VERSION 5.7 ;
  NOWIREEXTENSIONATPIN ON ;
  DIVIDERCHAR "/" ;
  BUSBITCHARS "[]" ;
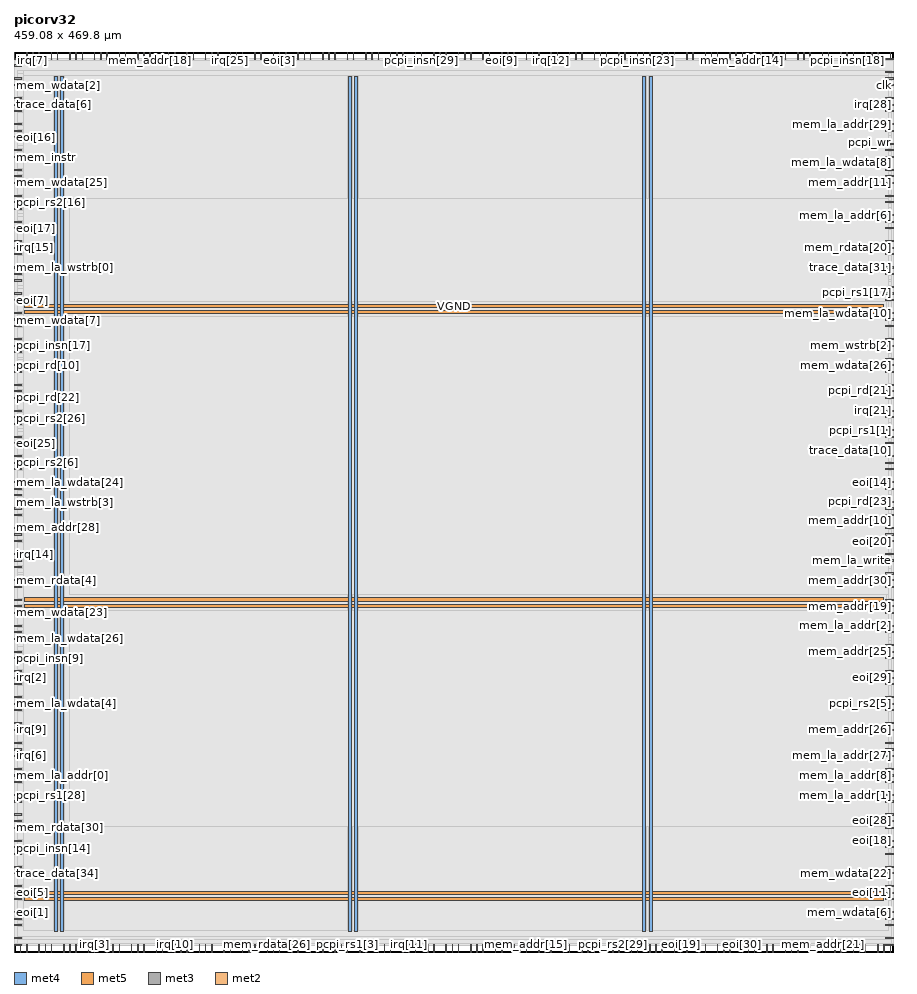
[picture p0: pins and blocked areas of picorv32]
MACRO picorv32
  CLASS BLOCK ;
  FOREIGN picorv32 ;
  ORIGIN 0.000 0.000 ;
  SIZE 459.080 BY 469.800 ;
  PIN VGND
    DIRECTION INOUT ;
    USE GROUND ;
    PORT
      LAYER met4 ;
        RECT 24.340 10.640 25.940 457.200 ;
    END
    PORT
      LAYER met4 ;
        RECT 177.940 10.640 179.540 457.200 ;
    END
    PORT
      LAYER met4 ;
        RECT 331.540 10.640 333.140 457.200 ;
    END
    PORT
      LAYER met5 ;
        RECT 5.280 30.030 453.800 31.630 ;
    END
    PORT
      LAYER met5 ;
        RECT 5.280 183.210 453.800 184.810 ;
    END
    PORT
      LAYER met5 ;
        RECT 5.280 336.390 453.800 337.990 ;
    END
  END VGND
  PIN VPWR
    DIRECTION INOUT ;
    USE POWER ;
    PORT
      LAYER met4 ;
        RECT 21.040 10.640 22.640 457.200 ;
    END
    PORT
      LAYER met4 ;
        RECT 174.640 10.640 176.240 457.200 ;
    END
    PORT
      LAYER met4 ;
        RECT 328.240 10.640 329.840 457.200 ;
    END
    PORT
      LAYER met5 ;
        RECT 5.280 26.730 453.800 28.330 ;
    END
    PORT
      LAYER met5 ;
        RECT 5.280 179.910 453.800 181.510 ;
    END
    PORT
      LAYER met5 ;
        RECT 5.280 333.090 453.800 334.690 ;
    END
  END VPWR
  PIN clk
    DIRECTION INPUT ;
    USE SIGNAL ;
    ANTENNAGATEAREA 1.286700 ;
    ANTENNADIFFAREA 0.434700 ;
    PORT
      LAYER met3 ;
        RECT 455.080 452.240 459.080 452.840 ;
    END
  END clk
  PIN eoi[0]
    DIRECTION OUTPUT TRISTATE ;
    USE SIGNAL ;
    PORT
      LAYER met3 ;
        RECT 0.000 455.640 4.000 456.240 ;
    END
  END eoi[0]
  PIN eoi[10]
    DIRECTION OUTPUT TRISTATE ;
    USE SIGNAL ;
    PORT
      LAYER met2 ;
        RECT 122.450 0.000 122.730 4.000 ;
    END
  END eoi[10]
  PIN eoi[11]
    DIRECTION OUTPUT TRISTATE ;
    USE SIGNAL ;
    PORT
      LAYER met3 ;
        RECT 455.080 30.640 459.080 31.240 ;
    END
  END eoi[11]
  PIN eoi[12]
    DIRECTION OUTPUT TRISTATE ;
    USE SIGNAL ;
    PORT
      LAYER met3 ;
        RECT 455.080 292.440 459.080 293.040 ;
    END
  END eoi[12]
  PIN eoi[13]
    DIRECTION OUTPUT TRISTATE ;
    USE SIGNAL ;
    PORT
      LAYER met2 ;
        RECT 396.150 465.800 396.430 469.800 ;
    END
  END eoi[13]
  PIN eoi[14]
    DIRECTION OUTPUT TRISTATE ;
    USE SIGNAL ;
    PORT
      LAYER met3 ;
        RECT 455.080 244.840 459.080 245.440 ;
    END
  END eoi[14]
  PIN eoi[15]
    DIRECTION OUTPUT TRISTATE ;
    USE SIGNAL ;
    PORT
      LAYER met3 ;
        RECT 455.080 78.240 459.080 78.840 ;
    END
  END eoi[15]
  PIN eoi[16]
    DIRECTION OUTPUT TRISTATE ;
    USE SIGNAL ;
    PORT
      LAYER met3 ;
        RECT 0.000 425.040 4.000 425.640 ;
    END
  END eoi[16]
  PIN eoi[17]
    DIRECTION OUTPUT TRISTATE ;
    USE SIGNAL ;
    PORT
      LAYER met3 ;
        RECT 0.000 377.440 4.000 378.040 ;
    END
  END eoi[17]
  PIN eoi[18]
    DIRECTION OUTPUT TRISTATE ;
    USE SIGNAL ;
    PORT
      LAYER met3 ;
        RECT 455.080 57.840 459.080 58.440 ;
    END
  END eoi[18]
  PIN eoi[19]
    DIRECTION OUTPUT TRISTATE ;
    USE SIGNAL ;
    PORT
      LAYER met2 ;
        RECT 347.850 0.000 348.130 4.000 ;
    END
  END eoi[19]
  PIN eoi[1]
    DIRECTION OUTPUT TRISTATE ;
    USE SIGNAL ;
    PORT
      LAYER met3 ;
        RECT 0.000 20.440 4.000 21.040 ;
    END
  END eoi[1]
  PIN eoi[20]
    DIRECTION OUTPUT TRISTATE ;
    USE SIGNAL ;
    PORT
      LAYER met3 ;
        RECT 455.080 214.240 459.080 214.840 ;
    END
  END eoi[20]
  PIN eoi[21]
    DIRECTION OUTPUT TRISTATE ;
    USE SIGNAL ;
    PORT
      LAYER met2 ;
        RECT 457.330 0.000 457.610 4.000 ;
    END
  END eoi[21]
  PIN eoi[22]
    DIRECTION OUTPUT TRISTATE ;
    USE SIGNAL ;
    PORT
      LAYER met3 ;
        RECT 0.000 428.440 4.000 429.040 ;
    END
  END eoi[22]
  PIN eoi[23]
    DIRECTION OUTPUT TRISTATE ;
    USE SIGNAL ;
    PORT
      LAYER met3 ;
        RECT 455.080 88.440 459.080 89.040 ;
    END
  END eoi[23]
  PIN eoi[24]
    DIRECTION OUTPUT TRISTATE ;
    USE SIGNAL ;
    PORT
      LAYER met2 ;
        RECT 51.610 0.000 51.890 4.000 ;
    END
  END eoi[24]
  PIN eoi[25]
    DIRECTION OUTPUT TRISTATE ;
    USE SIGNAL ;
    PORT
      LAYER met3 ;
        RECT 0.000 265.240 4.000 265.840 ;
    END
  END eoi[25]
  PIN eoi[26]
    DIRECTION OUTPUT TRISTATE ;
    USE SIGNAL ;
    PORT
      LAYER met2 ;
        RECT 190.070 465.800 190.350 469.800 ;
    END
  END eoi[26]
  PIN eoi[27]
    DIRECTION OUTPUT TRISTATE ;
    USE SIGNAL ;
    PORT
      LAYER met3 ;
        RECT 0.000 34.040 4.000 34.640 ;
    END
  END eoi[27]
  PIN eoi[28]
    DIRECTION OUTPUT TRISTATE ;
    USE SIGNAL ;
    PORT
      LAYER met3 ;
        RECT 455.080 64.640 459.080 65.240 ;
    END
  END eoi[28]
  PIN eoi[29]
    DIRECTION OUTPUT TRISTATE ;
    USE SIGNAL ;
    PORT
      LAYER met3 ;
        RECT 455.080 142.840 459.080 143.440 ;
    END
  END eoi[29]
  PIN eoi[2]
    DIRECTION OUTPUT TRISTATE ;
    USE SIGNAL ;
    PORT
      LAYER met3 ;
        RECT 455.080 353.640 459.080 354.240 ;
    END
  END eoi[2]
  PIN eoi[30]
    DIRECTION OUTPUT TRISTATE ;
    USE SIGNAL ;
    PORT
      LAYER met2 ;
        RECT 380.050 0.000 380.330 4.000 ;
    END
  END eoi[30]
  PIN eoi[31]
    DIRECTION OUTPUT TRISTATE ;
    USE SIGNAL ;
    PORT
      LAYER met3 ;
        RECT 455.080 241.440 459.080 242.040 ;
    END
  END eoi[31]
  PIN eoi[3]
    DIRECTION OUTPUT TRISTATE ;
    USE SIGNAL ;
    PORT
      LAYER met2 ;
        RECT 138.550 465.800 138.830 469.800 ;
    END
  END eoi[3]
  PIN eoi[4]
    DIRECTION OUTPUT TRISTATE ;
    USE SIGNAL ;
    PORT
      LAYER met2 ;
        RECT 373.610 0.000 373.890 4.000 ;
    END
  END eoi[4]
  PIN eoi[5]
    DIRECTION OUTPUT TRISTATE ;
    USE SIGNAL ;
    PORT
      LAYER met3 ;
        RECT 0.000 30.640 4.000 31.240 ;
    END
  END eoi[5]
  PIN eoi[6]
    DIRECTION OUTPUT TRISTATE ;
    USE SIGNAL ;
    PORT
      LAYER met2 ;
        RECT 360.730 0.000 361.010 4.000 ;
    END
  END eoi[6]
  PIN eoi[7]
    DIRECTION OUTPUT TRISTATE ;
    USE SIGNAL ;
    PORT
      LAYER met3 ;
        RECT 0.000 340.040 4.000 340.640 ;
    END
  END eoi[7]
  PIN eoi[8]
    DIRECTION OUTPUT TRISTATE ;
    USE SIGNAL ;
    PORT
      LAYER met2 ;
        RECT 338.190 465.800 338.470 469.800 ;
    END
  END eoi[8]
  PIN eoi[9]
    DIRECTION OUTPUT TRISTATE ;
    USE SIGNAL ;
    PORT
      LAYER met2 ;
        RECT 254.470 465.800 254.750 469.800 ;
    END
  END eoi[9]
  PIN irq[0]
    DIRECTION INPUT ;
    USE SIGNAL ;
    PORT
      LAYER met3 ;
        RECT 455.080 183.640 459.080 184.240 ;
    END
  END irq[0]
  PIN irq[10]
    DIRECTION INPUT ;
    USE SIGNAL ;
    PORT
      LAYER met2 ;
        RECT 83.810 0.000 84.090 4.000 ;
    END
  END irq[10]
  PIN irq[11]
    DIRECTION INPUT ;
    USE SIGNAL ;
    PORT
      LAYER met2 ;
        RECT 206.170 0.000 206.450 4.000 ;
    END
  END irq[11]
  PIN irq[12]
    DIRECTION INPUT ;
    USE SIGNAL ;
    PORT
      LAYER met2 ;
        RECT 280.230 465.800 280.510 469.800 ;
    END
  END irq[12]
  PIN irq[13]
    DIRECTION INPUT ;
    USE SIGNAL ;
    PORT
      LAYER met2 ;
        RECT 444.450 465.800 444.730 469.800 ;
    END
  END irq[13]
  PIN irq[14]
    DIRECTION INPUT ;
    USE SIGNAL ;
    PORT
      LAYER met3 ;
        RECT 0.000 207.440 4.000 208.040 ;
    END
  END irq[14]
  PIN irq[15]
    DIRECTION INPUT ;
    USE SIGNAL ;
    PORT
      LAYER met3 ;
        RECT 0.000 367.240 4.000 367.840 ;
    END
  END irq[15]
  PIN irq[16]
    DIRECTION INPUT ;
    USE SIGNAL ;
    PORT
      LAYER met2 ;
        RECT 457.330 465.800 457.610 469.800 ;
    END
  END irq[16]
  PIN irq[17]
    DIRECTION INPUT ;
    USE SIGNAL ;
    PORT
      LAYER met2 ;
        RECT 257.690 465.800 257.970 469.800 ;
    END
  END irq[17]
  PIN irq[18]
    DIRECTION INPUT ;
    USE SIGNAL ;
    PORT
      LAYER met2 ;
        RECT 344.630 465.800 344.910 469.800 ;
    END
  END irq[18]
  PIN irq[19]
    DIRECTION INPUT ;
    USE SIGNAL ;
    PORT
      LAYER met3 ;
        RECT 0.000 431.840 4.000 432.440 ;
    END
  END irq[19]
  PIN irq[1]
    DIRECTION INPUT ;
    USE SIGNAL ;
    PORT
      LAYER met2 ;
        RECT 309.210 0.000 309.490 4.000 ;
    END
  END irq[1]
  PIN irq[20]
    DIRECTION INPUT ;
    USE SIGNAL ;
    PORT
      LAYER met3 ;
        RECT 0.000 465.840 4.000 466.440 ;
    END
  END irq[20]
  PIN irq[21]
    DIRECTION INPUT ;
    USE SIGNAL ;
    PORT
      LAYER met3 ;
        RECT 455.080 282.240 459.080 282.840 ;
    END
  END irq[21]
  PIN irq[22]
    DIRECTION INPUT ;
    USE SIGNAL ;
    PORT
      LAYER met2 ;
        RECT 154.650 0.000 154.930 4.000 ;
    END
  END irq[22]
  PIN irq[23]
    DIRECTION INPUT ;
    USE SIGNAL ;
    PORT
      LAYER met3 ;
        RECT 0.000 275.440 4.000 276.040 ;
    END
  END irq[23]
  PIN irq[24]
    DIRECTION INPUT ;
    USE SIGNAL ;
    PORT
      LAYER met3 ;
        RECT 455.080 465.840 459.080 466.440 ;
    END
  END irq[24]
  PIN irq[25]
    DIRECTION INPUT ;
    USE SIGNAL ;
    PORT
      LAYER met2 ;
        RECT 112.790 465.800 113.070 469.800 ;
    END
  END irq[25]
  PIN irq[26]
    DIRECTION INPUT ;
    USE SIGNAL ;
    PORT
      LAYER met2 ;
        RECT 190.070 0.000 190.350 4.000 ;
    END
  END irq[26]
  PIN irq[27]
    DIRECTION INPUT ;
    USE SIGNAL ;
    PORT
      LAYER met2 ;
        RECT 231.930 465.800 232.210 469.800 ;
    END
  END irq[27]
  PIN irq[28]
    DIRECTION INPUT ;
    USE SIGNAL ;
    PORT
      LAYER met3 ;
        RECT 455.080 442.040 459.080 442.640 ;
    END
  END irq[28]
  PIN irq[29]
    DIRECTION INPUT ;
    USE SIGNAL ;
    PORT
      LAYER met3 ;
        RECT 455.080 54.440 459.080 55.040 ;
    END
  END irq[29]
  PIN irq[2]
    DIRECTION INPUT ;
    USE SIGNAL ;
    PORT
      LAYER met3 ;
        RECT 0.000 142.840 4.000 143.440 ;
    END
  END irq[2]
  PIN irq[30]
    DIRECTION INPUT ;
    USE SIGNAL ;
    PORT
      LAYER met2 ;
        RECT 264.130 0.000 264.410 4.000 ;
    END
  END irq[30]
  PIN irq[31]
    DIRECTION INPUT ;
    USE SIGNAL ;
    PORT
      LAYER met2 ;
        RECT 106.350 465.800 106.630 469.800 ;
    END
  END irq[31]
  PIN irq[3]
    DIRECTION INPUT ;
    USE SIGNAL ;
    PORT
      LAYER met2 ;
        RECT 41.950 0.000 42.230 4.000 ;
    END
  END irq[3]
  PIN irq[4]
    DIRECTION INPUT ;
    USE SIGNAL ;
    PORT
      LAYER met2 ;
        RECT 90.250 465.800 90.530 469.800 ;
    END
  END irq[4]
  PIN irq[5]
    DIRECTION INPUT ;
    USE SIGNAL ;
    PORT
      LAYER met3 ;
        RECT 455.080 414.840 459.080 415.440 ;
    END
  END irq[5]
  PIN irq[6]
    DIRECTION INPUT ;
    USE SIGNAL ;
    PORT
      LAYER met3 ;
        RECT 0.000 102.040 4.000 102.640 ;
    END
  END irq[6]
  PIN irq[7]
    DIRECTION INPUT ;
    USE SIGNAL ;
    PORT
      LAYER met2 ;
        RECT 9.750 465.800 10.030 469.800 ;
    END
  END irq[7]
  PIN irq[8]
    DIRECTION INPUT ;
    USE SIGNAL ;
    PORT
      LAYER met2 ;
        RECT 322.090 0.000 322.370 4.000 ;
    END
  END irq[8]
  PIN irq[9]
    DIRECTION INPUT ;
    USE SIGNAL ;
    PORT
      LAYER met3 ;
        RECT 0.000 115.640 4.000 116.240 ;
    END
  END irq[9]
  PIN mem_addr[0]
    DIRECTION OUTPUT TRISTATE ;
    USE SIGNAL ;
    PORT
      LAYER met3 ;
        RECT 455.080 13.640 459.080 14.240 ;
    END
  END mem_addr[0]
  PIN mem_addr[10]
    DIRECTION OUTPUT TRISTATE ;
    USE SIGNAL ;
    ANTENNADIFFAREA 0.795200 ;
    PORT
      LAYER met3 ;
        RECT 455.080 221.040 459.080 221.640 ;
    END
  END mem_addr[10]
  PIN mem_addr[11]
    DIRECTION OUTPUT TRISTATE ;
    USE SIGNAL ;
    ANTENNADIFFAREA 0.445500 ;
    PORT
      LAYER met3 ;
        RECT 455.080 401.240 459.080 401.840 ;
    END
  END mem_addr[11]
  PIN mem_addr[12]
    DIRECTION OUTPUT TRISTATE ;
    USE SIGNAL ;
    ANTENNADIFFAREA 0.445500 ;
    PORT
      LAYER met3 ;
        RECT 455.080 51.040 459.080 51.640 ;
    END
  END mem_addr[12]
  PIN mem_addr[13]
    DIRECTION OUTPUT TRISTATE ;
    USE SIGNAL ;
    ANTENNADIFFAREA 0.795200 ;
    PORT
      LAYER met2 ;
        RECT 267.350 465.800 267.630 469.800 ;
    END
  END mem_addr[13]
  PIN mem_addr[14]
    DIRECTION OUTPUT TRISTATE ;
    USE SIGNAL ;
    ANTENNADIFFAREA 0.795200 ;
    PORT
      LAYER met2 ;
        RECT 380.050 465.800 380.330 469.800 ;
    END
  END mem_addr[14]
  PIN mem_addr[15]
    DIRECTION OUTPUT TRISTATE ;
    USE SIGNAL ;
    ANTENNADIFFAREA 0.795200 ;
    PORT
      LAYER met2 ;
        RECT 267.350 0.000 267.630 4.000 ;
    END
  END mem_addr[15]
  PIN mem_addr[16]
    DIRECTION OUTPUT TRISTATE ;
    USE SIGNAL ;
    ANTENNADIFFAREA 0.795200 ;
    PORT
      LAYER met3 ;
        RECT 0.000 166.640 4.000 167.240 ;
    END
  END mem_addr[16]
  PIN mem_addr[17]
    DIRECTION OUTPUT TRISTATE ;
    USE SIGNAL ;
    ANTENNADIFFAREA 0.795200 ;
    PORT
      LAYER met3 ;
        RECT 0.000 200.640 4.000 201.240 ;
    END
  END mem_addr[17]
  PIN mem_addr[18]
    DIRECTION OUTPUT TRISTATE ;
    USE SIGNAL ;
    ANTENNADIFFAREA 0.795200 ;
    PORT
      LAYER met2 ;
        RECT 70.930 465.800 71.210 469.800 ;
    END
  END mem_addr[18]
  PIN mem_addr[19]
    DIRECTION OUTPUT TRISTATE ;
    USE SIGNAL ;
    ANTENNADIFFAREA 0.795200 ;
    PORT
      LAYER met3 ;
        RECT 455.080 180.240 459.080 180.840 ;
    END
  END mem_addr[19]
  PIN mem_addr[1]
    DIRECTION OUTPUT TRISTATE ;
    USE SIGNAL ;
    PORT
      LAYER met2 ;
        RECT 103.130 0.000 103.410 4.000 ;
    END
  END mem_addr[1]
  PIN mem_addr[20]
    DIRECTION OUTPUT TRISTATE ;
    USE SIGNAL ;
    ANTENNADIFFAREA 0.795200 ;
    PORT
      LAYER met3 ;
        RECT 0.000 6.840 4.000 7.440 ;
    END
  END mem_addr[20]
  PIN mem_addr[21]
    DIRECTION OUTPUT TRISTATE ;
    USE SIGNAL ;
    ANTENNADIFFAREA 0.795200 ;
    PORT
      LAYER met2 ;
        RECT 421.910 0.000 422.190 4.000 ;
    END
  END mem_addr[21]
  PIN mem_addr[22]
    DIRECTION OUTPUT TRISTATE ;
    USE SIGNAL ;
    ANTENNADIFFAREA 0.795200 ;
    PORT
      LAYER met2 ;
        RECT 277.010 0.000 277.290 4.000 ;
    END
  END mem_addr[22]
  PIN mem_addr[23]
    DIRECTION OUTPUT TRISTATE ;
    USE SIGNAL ;
    ANTENNADIFFAREA 0.795200 ;
    PORT
      LAYER met2 ;
        RECT 418.690 0.000 418.970 4.000 ;
    END
  END mem_addr[23]
  PIN mem_addr[24]
    DIRECTION OUTPUT TRISTATE ;
    USE SIGNAL ;
    ANTENNADIFFAREA 0.795200 ;
    PORT
      LAYER met2 ;
        RECT 248.030 465.800 248.310 469.800 ;
    END
  END mem_addr[24]
  PIN mem_addr[25]
    DIRECTION OUTPUT TRISTATE ;
    USE SIGNAL ;
    ANTENNADIFFAREA 0.795200 ;
    PORT
      LAYER met3 ;
        RECT 455.080 156.440 459.080 157.040 ;
    END
  END mem_addr[25]
  PIN mem_addr[26]
    DIRECTION OUTPUT TRISTATE ;
    USE SIGNAL ;
    ANTENNADIFFAREA 0.445500 ;
    PORT
      LAYER met3 ;
        RECT 455.080 115.640 459.080 116.240 ;
    END
  END mem_addr[26]
  PIN mem_addr[27]
    DIRECTION OUTPUT TRISTATE ;
    USE SIGNAL ;
    ANTENNADIFFAREA 0.795200 ;
    PORT
      LAYER met3 ;
        RECT 0.000 319.640 4.000 320.240 ;
    END
  END mem_addr[27]
  PIN mem_addr[28]
    DIRECTION OUTPUT TRISTATE ;
    USE SIGNAL ;
    ANTENNADIFFAREA 0.795200 ;
    PORT
      LAYER met3 ;
        RECT 0.000 221.040 4.000 221.640 ;
    END
  END mem_addr[28]
  PIN mem_addr[29]
    DIRECTION OUTPUT TRISTATE ;
    USE SIGNAL ;
    ANTENNADIFFAREA 0.795200 ;
    PORT
      LAYER met2 ;
        RECT 116.010 465.800 116.290 469.800 ;
    END
  END mem_addr[29]
  PIN mem_addr[2]
    DIRECTION OUTPUT TRISTATE ;
    USE SIGNAL ;
    ANTENNADIFFAREA 0.795200 ;
    PORT
      LAYER met2 ;
        RECT 180.410 0.000 180.690 4.000 ;
    END
  END mem_addr[2]
  PIN mem_addr[30]
    DIRECTION OUTPUT TRISTATE ;
    USE SIGNAL ;
    ANTENNADIFFAREA 0.795200 ;
    PORT
      LAYER met3 ;
        RECT 455.080 193.840 459.080 194.440 ;
    END
  END mem_addr[30]
  PIN mem_addr[31]
    DIRECTION OUTPUT TRISTATE ;
    USE SIGNAL ;
    ANTENNADIFFAREA 0.795200 ;
    PORT
      LAYER met3 ;
        RECT 0.000 438.640 4.000 439.240 ;
    END
  END mem_addr[31]
  PIN mem_addr[3]
    DIRECTION OUTPUT TRISTATE ;
    USE SIGNAL ;
    ANTENNADIFFAREA 0.795200 ;
    PORT
      LAYER met2 ;
        RECT 289.890 0.000 290.170 4.000 ;
    END
  END mem_addr[3]
  PIN mem_addr[4]
    DIRECTION OUTPUT TRISTATE ;
    USE SIGNAL ;
    ANTENNADIFFAREA 0.795200 ;
    PORT
      LAYER met3 ;
        RECT 0.000 329.840 4.000 330.440 ;
    END
  END mem_addr[4]
  PIN mem_addr[5]
    DIRECTION OUTPUT TRISTATE ;
    USE SIGNAL ;
    ANTENNADIFFAREA 0.795200 ;
    PORT
      LAYER met2 ;
        RECT 270.570 465.800 270.850 469.800 ;
    END
  END mem_addr[5]
  PIN mem_addr[6]
    DIRECTION OUTPUT TRISTATE ;
    USE SIGNAL ;
    ANTENNADIFFAREA 0.795200 ;
    PORT
      LAYER met2 ;
        RECT 22.630 465.800 22.910 469.800 ;
    END
  END mem_addr[6]
  PIN mem_addr[7]
    DIRECTION OUTPUT TRISTATE ;
    USE SIGNAL ;
    ANTENNADIFFAREA 0.445500 ;
    PORT
      LAYER met3 ;
        RECT 455.080 421.640 459.080 422.240 ;
    END
  END mem_addr[7]
  PIN mem_addr[8]
    DIRECTION OUTPUT TRISTATE ;
    USE SIGNAL ;
    ANTENNADIFFAREA 0.795200 ;
    PORT
      LAYER met2 ;
        RECT 29.070 0.000 29.350 4.000 ;
    END
  END mem_addr[8]
  PIN mem_addr[9]
    DIRECTION OUTPUT TRISTATE ;
    USE SIGNAL ;
    ANTENNADIFFAREA 0.795200 ;
    PORT
      LAYER met3 ;
        RECT 0.000 445.440 4.000 446.040 ;
    END
  END mem_addr[9]
  PIN mem_instr
    DIRECTION OUTPUT TRISTATE ;
    USE SIGNAL ;
    ANTENNADIFFAREA 0.795200 ;
    PORT
      LAYER met3 ;
        RECT 0.000 418.240 4.000 418.840 ;
    END
  END mem_instr
  PIN mem_la_addr[0]
    DIRECTION OUTPUT TRISTATE ;
    USE SIGNAL ;
    PORT
      LAYER met3 ;
        RECT 0.000 91.840 4.000 92.440 ;
    END
  END mem_la_addr[0]
  PIN mem_la_addr[10]
    DIRECTION OUTPUT TRISTATE ;
    USE SIGNAL ;
    ANTENNADIFFAREA 0.795200 ;
    PORT
      LAYER met3 ;
        RECT 455.080 255.040 459.080 255.640 ;
    END
  END mem_la_addr[10]
  PIN mem_la_addr[11]
    DIRECTION OUTPUT TRISTATE ;
    USE SIGNAL ;
    ANTENNADIFFAREA 0.795200 ;
    PORT
      LAYER met2 ;
        RECT 0.090 465.800 0.370 469.800 ;
    END
  END mem_la_addr[11]
  PIN mem_la_addr[12]
    DIRECTION OUTPUT TRISTATE ;
    USE SIGNAL ;
    ANTENNADIFFAREA 0.445500 ;
    PORT
      LAYER met2 ;
        RECT 154.650 465.800 154.930 469.800 ;
    END
  END mem_la_addr[12]
  PIN mem_la_addr[13]
    DIRECTION OUTPUT TRISTATE ;
    USE SIGNAL ;
    ANTENNADIFFAREA 0.795200 ;
    PORT
      LAYER met2 ;
        RECT 219.050 0.000 219.330 4.000 ;
    END
  END mem_la_addr[13]
  PIN mem_la_addr[14]
    DIRECTION OUTPUT TRISTATE ;
    USE SIGNAL ;
    ANTENNADIFFAREA 0.795200 ;
    PORT
      LAYER met3 ;
        RECT 0.000 44.240 4.000 44.840 ;
    END
  END mem_la_addr[14]
  PIN mem_la_addr[15]
    DIRECTION OUTPUT TRISTATE ;
    USE SIGNAL ;
    ANTENNADIFFAREA 0.795200 ;
    PORT
      LAYER met2 ;
        RECT 293.110 465.800 293.390 469.800 ;
    END
  END mem_la_addr[15]
  PIN mem_la_addr[16]
    DIRECTION OUTPUT TRISTATE ;
    USE SIGNAL ;
    ANTENNADIFFAREA 0.445500 ;
    PORT
      LAYER met3 ;
        RECT 455.080 319.640 459.080 320.240 ;
    END
  END mem_la_addr[16]
  PIN mem_la_addr[17]
    DIRECTION OUTPUT TRISTATE ;
    USE SIGNAL ;
    ANTENNADIFFAREA 0.795200 ;
    PORT
      LAYER met2 ;
        RECT 6.530 465.800 6.810 469.800 ;
    END
  END mem_la_addr[17]
  PIN mem_la_addr[18]
    DIRECTION OUTPUT TRISTATE ;
    USE SIGNAL ;
    ANTENNADIFFAREA 0.795200 ;
    PORT
      LAYER met2 ;
        RECT 299.550 0.000 299.830 4.000 ;
    END
  END mem_la_addr[18]
  PIN mem_la_addr[19]
    DIRECTION OUTPUT TRISTATE ;
    USE SIGNAL ;
    ANTENNADIFFAREA 0.795200 ;
    PORT
      LAYER met2 ;
        RECT 438.010 0.000 438.290 4.000 ;
    END
  END mem_la_addr[19]
  PIN mem_la_addr[1]
    DIRECTION OUTPUT TRISTATE ;
    USE SIGNAL ;
    PORT
      LAYER met3 ;
        RECT 455.080 81.640 459.080 82.240 ;
    END
  END mem_la_addr[1]
  PIN mem_la_addr[20]
    DIRECTION OUTPUT TRISTATE ;
    USE SIGNAL ;
    ANTENNADIFFAREA 0.795200 ;
    PORT
      LAYER met2 ;
        RECT 12.970 465.800 13.250 469.800 ;
    END
  END mem_la_addr[20]
  PIN mem_la_addr[21]
    DIRECTION OUTPUT TRISTATE ;
    USE SIGNAL ;
    ANTENNADIFFAREA 0.795200 ;
    PORT
      LAYER met2 ;
        RECT 199.730 465.800 200.010 469.800 ;
    END
  END mem_la_addr[21]
  PIN mem_la_addr[22]
    DIRECTION OUTPUT TRISTATE ;
    USE SIGNAL ;
    ANTENNADIFFAREA 0.795200 ;
    PORT
      LAYER met3 ;
        RECT 0.000 258.440 4.000 259.040 ;
    END
  END mem_la_addr[22]
  PIN mem_la_addr[23]
    DIRECTION OUTPUT TRISTATE ;
    USE SIGNAL ;
    ANTENNADIFFAREA 0.795200 ;
    PORT
      LAYER met2 ;
        RECT 93.470 465.800 93.750 469.800 ;
    END
  END mem_la_addr[23]
  PIN mem_la_addr[24]
    DIRECTION OUTPUT TRISTATE ;
    USE SIGNAL ;
    ANTENNADIFFAREA 0.445500 ;
    PORT
      LAYER met2 ;
        RECT 64.490 465.800 64.770 469.800 ;
    END
  END mem_la_addr[24]
  PIN mem_la_addr[25]
    DIRECTION OUTPUT TRISTATE ;
    USE SIGNAL ;
    ANTENNADIFFAREA 0.445500 ;
    PORT
      LAYER met3 ;
        RECT 455.080 394.440 459.080 395.040 ;
    END
  END mem_la_addr[25]
  PIN mem_la_addr[26]
    DIRECTION OUTPUT TRISTATE ;
    USE SIGNAL ;
    ANTENNADIFFAREA 0.445500 ;
    PORT
      LAYER met2 ;
        RECT 58.050 465.800 58.330 469.800 ;
    END
  END mem_la_addr[26]
  PIN mem_la_addr[27]
    DIRECTION OUTPUT TRISTATE ;
    USE SIGNAL ;
    ANTENNADIFFAREA 0.445500 ;
    PORT
      LAYER met3 ;
        RECT 455.080 102.040 459.080 102.640 ;
    END
  END mem_la_addr[27]
  PIN mem_la_addr[28]
    DIRECTION OUTPUT TRISTATE ;
    USE SIGNAL ;
    ANTENNADIFFAREA 0.795200 ;
    PORT
      LAYER met2 ;
        RECT 29.070 465.800 29.350 469.800 ;
    END
  END mem_la_addr[28]
  PIN mem_la_addr[29]
    DIRECTION OUTPUT TRISTATE ;
    USE SIGNAL ;
    ANTENNADIFFAREA 0.445500 ;
    PORT
      LAYER met3 ;
        RECT 455.080 431.840 459.080 432.440 ;
    END
  END mem_la_addr[29]
  PIN mem_la_addr[2]
    DIRECTION OUTPUT TRISTATE ;
    USE SIGNAL ;
    ANTENNADIFFAREA 0.445500 ;
    PORT
      LAYER met3 ;
        RECT 455.080 170.040 459.080 170.640 ;
    END
  END mem_la_addr[2]
  PIN mem_la_addr[30]
    DIRECTION OUTPUT TRISTATE ;
    USE SIGNAL ;
    ANTENNADIFFAREA 0.795200 ;
    PORT
      LAYER met3 ;
        RECT 0.000 278.840 4.000 279.440 ;
    END
  END mem_la_addr[30]
  PIN mem_la_addr[31]
    DIRECTION OUTPUT TRISTATE ;
    USE SIGNAL ;
    ANTENNADIFFAREA 0.795200 ;
    PORT
      LAYER met2 ;
        RECT 161.090 0.000 161.370 4.000 ;
    END
  END mem_la_addr[31]
  PIN mem_la_addr[3]
    DIRECTION OUTPUT TRISTATE ;
    USE SIGNAL ;
    ANTENNADIFFAREA 0.795200 ;
    PORT
      LAYER met3 ;
        RECT 0.000 13.640 4.000 14.240 ;
    END
  END mem_la_addr[3]
  PIN mem_la_addr[4]
    DIRECTION OUTPUT TRISTATE ;
    USE SIGNAL ;
    ANTENNADIFFAREA 0.445500 ;
    PORT
      LAYER met3 ;
        RECT 455.080 377.440 459.080 378.040 ;
    END
  END mem_la_addr[4]
  PIN mem_la_addr[5]
    DIRECTION OUTPUT TRISTATE ;
    USE SIGNAL ;
    ANTENNADIFFAREA 0.795200 ;
    PORT
      LAYER met2 ;
        RECT 383.270 0.000 383.550 4.000 ;
    END
  END mem_la_addr[5]
  PIN mem_la_addr[6]
    DIRECTION OUTPUT TRISTATE ;
    USE SIGNAL ;
    ANTENNADIFFAREA 0.795200 ;
    PORT
      LAYER met3 ;
        RECT 455.080 384.240 459.080 384.840 ;
    END
  END mem_la_addr[6]
  PIN mem_la_addr[7]
    DIRECTION OUTPUT TRISTATE ;
    USE SIGNAL ;
    ANTENNADIFFAREA 0.795200 ;
    PORT
      LAYER met2 ;
        RECT 135.330 0.000 135.610 4.000 ;
    END
  END mem_la_addr[7]
  PIN mem_la_addr[8]
    DIRECTION OUTPUT TRISTATE ;
    USE SIGNAL ;
    ANTENNADIFFAREA 0.795200 ;
    PORT
      LAYER met3 ;
        RECT 455.080 91.840 459.080 92.440 ;
    END
  END mem_la_addr[8]
  PIN mem_la_addr[9]
    DIRECTION OUTPUT TRISTATE ;
    USE SIGNAL ;
    ANTENNADIFFAREA 0.795200 ;
    PORT
      LAYER met2 ;
        RECT 144.990 0.000 145.270 4.000 ;
    END
  END mem_la_addr[9]
  PIN mem_la_read
    DIRECTION OUTPUT TRISTATE ;
    USE SIGNAL ;
    ANTENNADIFFAREA 0.445500 ;
    PORT
      LAYER met3 ;
        RECT 455.080 105.440 459.080 106.040 ;
    END
  END mem_la_read
  PIN mem_la_wdata[0]
    DIRECTION OUTPUT TRISTATE ;
    USE SIGNAL ;
    ANTENNADIFFAREA 0.795200 ;
    PORT
      LAYER met2 ;
        RECT 402.590 465.800 402.870 469.800 ;
    END
  END mem_la_wdata[0]
  PIN mem_la_wdata[10]
    DIRECTION OUTPUT TRISTATE ;
    USE SIGNAL ;
    ANTENNADIFFAREA 0.795200 ;
    PORT
      LAYER met3 ;
        RECT 455.080 333.240 459.080 333.840 ;
    END
  END mem_la_wdata[10]
  PIN mem_la_wdata[11]
    DIRECTION OUTPUT TRISTATE ;
    USE SIGNAL ;
    ANTENNADIFFAREA 0.795200 ;
    PORT
      LAYER met2 ;
        RECT 222.270 465.800 222.550 469.800 ;
    END
  END mem_la_wdata[11]
  PIN mem_la_wdata[12]
    DIRECTION OUTPUT TRISTATE ;
    USE SIGNAL ;
    ANTENNADIFFAREA 0.795200 ;
    PORT
      LAYER met2 ;
        RECT 80.590 465.800 80.870 469.800 ;
    END
  END mem_la_wdata[12]
  PIN mem_la_wdata[13]
    DIRECTION OUTPUT TRISTATE ;
    USE SIGNAL ;
    ANTENNADIFFAREA 0.795200 ;
    PORT
      LAYER met2 ;
        RECT 331.750 0.000 332.030 4.000 ;
    END
  END mem_la_wdata[13]
  PIN mem_la_wdata[14]
    DIRECTION OUTPUT TRISTATE ;
    USE SIGNAL ;
    ANTENNADIFFAREA 0.795200 ;
    PORT
      LAYER met3 ;
        RECT 0.000 380.840 4.000 381.440 ;
    END
  END mem_la_wdata[14]
  PIN mem_la_wdata[15]
    DIRECTION OUTPUT TRISTATE ;
    USE SIGNAL ;
    ANTENNADIFFAREA 0.795200 ;
    PORT
      LAYER met2 ;
        RECT 177.190 465.800 177.470 469.800 ;
    END
  END mem_la_wdata[15]
  PIN mem_la_wdata[16]
    DIRECTION OUTPUT TRISTATE ;
    USE SIGNAL ;
    ANTENNADIFFAREA 0.795200 ;
    PORT
      LAYER met2 ;
        RECT 376.830 465.800 377.110 469.800 ;
    END
  END mem_la_wdata[16]
  PIN mem_la_wdata[17]
    DIRECTION OUTPUT TRISTATE ;
    USE SIGNAL ;
    ANTENNADIFFAREA 0.795200 ;
    PORT
      LAYER met2 ;
        RECT 421.910 465.800 422.190 469.800 ;
    END
  END mem_la_wdata[17]
  PIN mem_la_wdata[18]
    DIRECTION OUTPUT TRISTATE ;
    USE SIGNAL ;
    ANTENNADIFFAREA 0.795200 ;
    PORT
      LAYER met3 ;
        RECT 0.000 217.640 4.000 218.240 ;
    END
  END mem_la_wdata[18]
  PIN mem_la_wdata[19]
    DIRECTION OUTPUT TRISTATE ;
    USE SIGNAL ;
    ANTENNADIFFAREA 0.795200 ;
    PORT
      LAYER met2 ;
        RECT 148.210 0.000 148.490 4.000 ;
    END
  END mem_la_wdata[19]
  PIN mem_la_wdata[1]
    DIRECTION OUTPUT TRISTATE ;
    USE SIGNAL ;
    ANTENNADIFFAREA 0.795200 ;
    PORT
      LAYER met2 ;
        RECT 209.390 0.000 209.670 4.000 ;
    END
  END mem_la_wdata[1]
  PIN mem_la_wdata[20]
    DIRECTION OUTPUT TRISTATE ;
    USE SIGNAL ;
    ANTENNADIFFAREA 0.795200 ;
    PORT
      LAYER met3 ;
        RECT 455.080 329.840 459.080 330.440 ;
    END
  END mem_la_wdata[20]
  PIN mem_la_wdata[21]
    DIRECTION OUTPUT TRISTATE ;
    USE SIGNAL ;
    ANTENNADIFFAREA 0.795200 ;
    PORT
      LAYER met3 ;
        RECT 455.080 268.640 459.080 269.240 ;
    END
  END mem_la_wdata[21]
  PIN mem_la_wdata[22]
    DIRECTION OUTPUT TRISTATE ;
    USE SIGNAL ;
    ANTENNADIFFAREA 0.795200 ;
    PORT
      LAYER met2 ;
        RECT 444.450 0.000 444.730 4.000 ;
    END
  END mem_la_wdata[22]
  PIN mem_la_wdata[23]
    DIRECTION OUTPUT TRISTATE ;
    USE SIGNAL ;
    ANTENNADIFFAREA 0.445500 ;
    PORT
      LAYER met3 ;
        RECT 455.080 326.440 459.080 327.040 ;
    END
  END mem_la_wdata[23]
  PIN mem_la_wdata[24]
    DIRECTION OUTPUT TRISTATE ;
    USE SIGNAL ;
    ANTENNADIFFAREA 0.795200 ;
    PORT
      LAYER met3 ;
        RECT 0.000 244.840 4.000 245.440 ;
    END
  END mem_la_wdata[24]
  PIN mem_la_wdata[25]
    DIRECTION OUTPUT TRISTATE ;
    USE SIGNAL ;
    ANTENNADIFFAREA 0.795200 ;
    PORT
      LAYER met3 ;
        RECT 0.000 51.040 4.000 51.640 ;
    END
  END mem_la_wdata[25]
  PIN mem_la_wdata[26]
    DIRECTION OUTPUT TRISTATE ;
    USE SIGNAL ;
    ANTENNADIFFAREA 0.795200 ;
    PORT
      LAYER met3 ;
        RECT 0.000 163.240 4.000 163.840 ;
    END
  END mem_la_wdata[26]
  PIN mem_la_wdata[27]
    DIRECTION OUTPUT TRISTATE ;
    USE SIGNAL ;
    ANTENNADIFFAREA 0.795200 ;
    PORT
      LAYER met2 ;
        RECT 309.210 465.800 309.490 469.800 ;
    END
  END mem_la_wdata[27]
  PIN mem_la_wdata[28]
    DIRECTION OUTPUT TRISTATE ;
    USE SIGNAL ;
    ANTENNADIFFAREA 0.795200 ;
    PORT
      LAYER met2 ;
        RECT 109.570 0.000 109.850 4.000 ;
    END
  END mem_la_wdata[28]
  PIN mem_la_wdata[29]
    DIRECTION OUTPUT TRISTATE ;
    USE SIGNAL ;
    ANTENNADIFFAREA 0.445500 ;
    PORT
      LAYER met2 ;
        RECT 196.510 465.800 196.790 469.800 ;
    END
  END mem_la_wdata[29]
  PIN mem_la_wdata[2]
    DIRECTION OUTPUT TRISTATE ;
    USE SIGNAL ;
    ANTENNADIFFAREA 0.795200 ;
    PORT
      LAYER met2 ;
        RECT 202.950 0.000 203.230 4.000 ;
    END
  END mem_la_wdata[2]
  PIN mem_la_wdata[30]
    DIRECTION OUTPUT TRISTATE ;
    USE SIGNAL ;
    ANTENNADIFFAREA 0.445500 ;
    PORT
      LAYER met3 ;
        RECT 455.080 132.640 459.080 133.240 ;
    END
  END mem_la_wdata[30]
  PIN mem_la_wdata[31]
    DIRECTION OUTPUT TRISTATE ;
    USE SIGNAL ;
    ANTENNADIFFAREA 0.795200 ;
    PORT
      LAYER met2 ;
        RECT 32.290 465.800 32.570 469.800 ;
    END
  END mem_la_wdata[31]
  PIN mem_la_wdata[3]
    DIRECTION OUTPUT TRISTATE ;
    USE SIGNAL ;
    ANTENNADIFFAREA 0.445500 ;
    PORT
      LAYER met3 ;
        RECT 455.080 108.840 459.080 109.440 ;
    END
  END mem_la_wdata[3]
  PIN mem_la_wdata[4]
    DIRECTION OUTPUT TRISTATE ;
    USE SIGNAL ;
    ANTENNADIFFAREA 0.795200 ;
    PORT
      LAYER met3 ;
        RECT 0.000 129.240 4.000 129.840 ;
    END
  END mem_la_wdata[4]
  PIN mem_la_wdata[5]
    DIRECTION OUTPUT TRISTATE ;
    USE SIGNAL ;
    ANTENNADIFFAREA 0.795200 ;
    PORT
      LAYER met2 ;
        RECT 296.330 0.000 296.610 4.000 ;
    END
  END mem_la_wdata[5]
  PIN mem_la_wdata[6]
    DIRECTION OUTPUT TRISTATE ;
    USE SIGNAL ;
    ANTENNADIFFAREA 0.795200 ;
    PORT
      LAYER met3 ;
        RECT 455.080 455.640 459.080 456.240 ;
    END
  END mem_la_wdata[6]
  PIN mem_la_wdata[7]
    DIRECTION OUTPUT TRISTATE ;
    USE SIGNAL ;
    ANTENNADIFFAREA 0.795200 ;
    PORT
      LAYER met2 ;
        RECT 157.870 0.000 158.150 4.000 ;
    END
  END mem_la_wdata[7]
  PIN mem_la_wdata[8]
    DIRECTION OUTPUT TRISTATE ;
    USE SIGNAL ;
    ANTENNADIFFAREA 0.445500 ;
    PORT
      LAYER met3 ;
        RECT 455.080 408.040 459.080 408.640 ;
    END
  END mem_la_wdata[8]
  PIN mem_la_wdata[9]
    DIRECTION OUTPUT TRISTATE ;
    USE SIGNAL ;
    ANTENNADIFFAREA 0.795200 ;
    PORT
      LAYER met3 ;
        RECT 0.000 204.040 4.000 204.640 ;
    END
  END mem_la_wdata[9]
  PIN mem_la_write
    DIRECTION OUTPUT TRISTATE ;
    USE SIGNAL ;
    ANTENNADIFFAREA 0.445500 ;
    PORT
      LAYER met3 ;
        RECT 455.080 204.040 459.080 204.640 ;
    END
  END mem_la_write
  PIN mem_la_wstrb[0]
    DIRECTION OUTPUT TRISTATE ;
    USE SIGNAL ;
    ANTENNADIFFAREA 0.795200 ;
    PORT
      LAYER met3 ;
        RECT 0.000 357.040 4.000 357.640 ;
    END
  END mem_la_wstrb[0]
  PIN mem_la_wstrb[1]
    DIRECTION OUTPUT TRISTATE ;
    USE SIGNAL ;
    ANTENNADIFFAREA 0.795200 ;
    PORT
      LAYER met3 ;
        RECT 0.000 292.440 4.000 293.040 ;
    END
  END mem_la_wstrb[1]
  PIN mem_la_wstrb[2]
    DIRECTION OUTPUT TRISTATE ;
    USE SIGNAL ;
    ANTENNADIFFAREA 0.795200 ;
    PORT
      LAYER met2 ;
        RECT 328.530 465.800 328.810 469.800 ;
    END
  END mem_la_wstrb[2]
  PIN mem_la_wstrb[3]
    DIRECTION OUTPUT TRISTATE ;
    USE SIGNAL ;
    ANTENNADIFFAREA 0.795200 ;
    PORT
      LAYER met3 ;
        RECT 0.000 238.040 4.000 238.640 ;
    END
  END mem_la_wstrb[3]
  PIN mem_rdata[0]
    DIRECTION INPUT ;
    USE SIGNAL ;
    ANTENNAGATEAREA 0.213000 ;
    PORT
      LAYER met3 ;
        RECT 0.000 251.640 4.000 252.240 ;
    END
  END mem_rdata[0]
  PIN mem_rdata[10]
    DIRECTION INPUT ;
    USE SIGNAL ;
    ANTENNAGATEAREA 0.159000 ;
    PORT
      LAYER met2 ;
        RECT 241.590 0.000 241.870 4.000 ;
    END
  END mem_rdata[10]
  PIN mem_rdata[11]
    DIRECTION INPUT ;
    USE SIGNAL ;
    ANTENNAGATEAREA 0.213000 ;
    PORT
      LAYER met2 ;
        RECT 405.810 0.000 406.090 4.000 ;
    END
  END mem_rdata[11]
  PIN mem_rdata[12]
    DIRECTION INPUT ;
    USE SIGNAL ;
    ANTENNAGATEAREA 0.213000 ;
    PORT
      LAYER met3 ;
        RECT 0.000 108.840 4.000 109.440 ;
    END
  END mem_rdata[12]
  PIN mem_rdata[13]
    DIRECTION INPUT ;
    USE SIGNAL ;
    ANTENNAGATEAREA 0.213000 ;
    PORT
      LAYER met2 ;
        RECT 103.130 465.800 103.410 469.800 ;
    END
  END mem_rdata[13]
  PIN mem_rdata[14]
    DIRECTION INPUT ;
    USE SIGNAL ;
    ANTENNAGATEAREA 0.213000 ;
    PORT
      LAYER met2 ;
        RECT 315.650 0.000 315.930 4.000 ;
    END
  END mem_rdata[14]
  PIN mem_rdata[15]
    DIRECTION INPUT ;
    USE SIGNAL ;
    ANTENNAGATEAREA 0.213000 ;
    PORT
      LAYER met3 ;
        RECT 0.000 350.240 4.000 350.840 ;
    END
  END mem_rdata[15]
  PIN mem_rdata[16]
    DIRECTION INPUT ;
    USE SIGNAL ;
    ANTENNAGATEAREA 0.159000 ;
    PORT
      LAYER met2 ;
        RECT 167.530 0.000 167.810 4.000 ;
    END
  END mem_rdata[16]
  PIN mem_rdata[17]
    DIRECTION INPUT ;
    USE SIGNAL ;
    ANTENNAGATEAREA 0.247500 ;
    PORT
      LAYER met3 ;
        RECT 455.080 176.840 459.080 177.440 ;
    END
  END mem_rdata[17]
  PIN mem_rdata[18]
    DIRECTION INPUT ;
    USE SIGNAL ;
    ANTENNAGATEAREA 0.213000 ;
    PORT
      LAYER met2 ;
        RECT 83.810 465.800 84.090 469.800 ;
    END
  END mem_rdata[18]
  PIN mem_rdata[19]
    DIRECTION INPUT ;
    USE SIGNAL ;
    ANTENNAGATEAREA 0.247500 ;
    PORT
      LAYER met2 ;
        RECT 235.150 465.800 235.430 469.800 ;
    END
  END mem_rdata[19]
  PIN mem_rdata[1]
    DIRECTION INPUT ;
    USE SIGNAL ;
    ANTENNAGATEAREA 0.247500 ;
    PORT
      LAYER met2 ;
        RECT 238.370 465.800 238.650 469.800 ;
    END
  END mem_rdata[1]
  PIN mem_rdata[20]
    DIRECTION INPUT ;
    USE SIGNAL ;
    ANTENNAGATEAREA 0.426000 ;
    PORT
      LAYER met3 ;
        RECT 455.080 367.240 459.080 367.840 ;
    END
  END mem_rdata[20]
  PIN mem_rdata[21]
    DIRECTION INPUT ;
    USE SIGNAL ;
    ANTENNAGATEAREA 0.247500 ;
    PORT
      LAYER met2 ;
        RECT 186.850 465.800 187.130 469.800 ;
    END
  END mem_rdata[21]
  PIN mem_rdata[22]
    DIRECTION INPUT ;
    USE SIGNAL ;
    ANTENNAGATEAREA 0.159000 ;
    PORT
      LAYER met3 ;
        RECT 0.000 183.640 4.000 184.240 ;
    END
  END mem_rdata[22]
  PIN mem_rdata[23]
    DIRECTION INPUT ;
    USE SIGNAL ;
    ANTENNAGATEAREA 0.247500 ;
    PORT
      LAYER met2 ;
        RECT 225.490 465.800 225.770 469.800 ;
    END
  END mem_rdata[23]
  PIN mem_rdata[24]
    DIRECTION INPUT ;
    USE SIGNAL ;
    ANTENNAGATEAREA 0.426000 ;
    PORT
      LAYER met2 ;
        RECT 373.610 465.800 373.890 469.800 ;
    END
  END mem_rdata[24]
  PIN mem_rdata[25]
    DIRECTION INPUT ;
    USE SIGNAL ;
    ANTENNAGATEAREA 0.159000 ;
    PORT
      LAYER met3 ;
        RECT 0.000 27.240 4.000 27.840 ;
    END
  END mem_rdata[25]
  PIN mem_rdata[26]
    DIRECTION INPUT ;
    USE SIGNAL ;
    ANTENNAGATEAREA 0.159000 ;
    PORT
      LAYER met2 ;
        RECT 132.110 0.000 132.390 4.000 ;
    END
  END mem_rdata[26]
  PIN mem_rdata[27]
    DIRECTION INPUT ;
    USE SIGNAL ;
    ANTENNAGATEAREA 0.247500 ;
    PORT
      LAYER met2 ;
        RECT 341.410 465.800 341.690 469.800 ;
    END
  END mem_rdata[27]
  PIN mem_rdata[28]
    DIRECTION INPUT ;
    USE SIGNAL ;
    ANTENNAGATEAREA 0.213000 ;
    PORT
      LAYER met2 ;
        RECT 238.370 0.000 238.650 4.000 ;
    END
  END mem_rdata[28]
  PIN mem_rdata[29]
    DIRECTION INPUT ;
    USE SIGNAL ;
    ANTENNAGATEAREA 0.426000 ;
    PORT
      LAYER met2 ;
        RECT 409.030 465.800 409.310 469.800 ;
    END
  END mem_rdata[29]
  PIN mem_rdata[2]
    DIRECTION INPUT ;
    USE SIGNAL ;
    ANTENNAGATEAREA 0.213000 ;
    PORT
      LAYER met2 ;
        RECT 61.270 0.000 61.550 4.000 ;
    END
  END mem_rdata[2]
  PIN mem_rdata[30]
    DIRECTION INPUT ;
    USE SIGNAL ;
    ANTENNAGATEAREA 0.159000 ;
    PORT
      LAYER met3 ;
        RECT 0.000 64.640 4.000 65.240 ;
    END
  END mem_rdata[30]
  PIN mem_rdata[31]
    DIRECTION INPUT ;
    USE SIGNAL ;
    ANTENNAGATEAREA 0.213000 ;
    PORT
      LAYER met2 ;
        RECT 193.290 0.000 193.570 4.000 ;
    END
  END mem_rdata[31]
  PIN mem_rdata[3]
    DIRECTION INPUT ;
    USE SIGNAL ;
    ANTENNAGATEAREA 0.213000 ;
    PORT
      LAYER met3 ;
        RECT 0.000 88.440 4.000 89.040 ;
    END
  END mem_rdata[3]
  PIN mem_rdata[4]
    DIRECTION INPUT ;
    USE SIGNAL ;
    ANTENNAGATEAREA 0.213000 ;
    PORT
      LAYER met3 ;
        RECT 0.000 193.840 4.000 194.440 ;
    END
  END mem_rdata[4]
  PIN mem_rdata[5]
    DIRECTION INPUT ;
    USE SIGNAL ;
    ANTENNAGATEAREA 0.213000 ;
    PORT
      LAYER met2 ;
        RECT 167.530 465.800 167.810 469.800 ;
    END
  END mem_rdata[5]
  PIN mem_rdata[6]
    DIRECTION INPUT ;
    USE SIGNAL ;
    ANTENNAGATEAREA 0.159000 ;
    PORT
      LAYER met3 ;
        RECT 0.000 363.840 4.000 364.440 ;
    END
  END mem_rdata[6]
  PIN mem_rdata[7]
    DIRECTION INPUT ;
    USE SIGNAL ;
    ANTENNAGATEAREA 0.213000 ;
    PORT
      LAYER met3 ;
        RECT 455.080 68.040 459.080 68.640 ;
    END
  END mem_rdata[7]
  PIN mem_rdata[8]
    DIRECTION INPUT ;
    USE SIGNAL ;
    ANTENNAGATEAREA 0.159000 ;
    PORT
      LAYER met2 ;
        RECT 215.830 0.000 216.110 4.000 ;
    END
  END mem_rdata[8]
  PIN mem_rdata[9]
    DIRECTION INPUT ;
    USE SIGNAL ;
    ANTENNAGATEAREA 0.247500 ;
    PORT
      LAYER met2 ;
        RECT 260.910 465.800 261.190 469.800 ;
    END
  END mem_rdata[9]
  PIN mem_ready
    DIRECTION INPUT ;
    USE SIGNAL ;
    ANTENNAGATEAREA 0.196500 ;
    PORT
      LAYER met3 ;
        RECT 0.000 214.240 4.000 214.840 ;
    END
  END mem_ready
  PIN mem_valid
    DIRECTION OUTPUT TRISTATE ;
    USE SIGNAL ;
    ANTENNADIFFAREA 0.795200 ;
    PORT
      LAYER met3 ;
        RECT 455.080 166.640 459.080 167.240 ;
    END
  END mem_valid
  PIN mem_wdata[0]
    DIRECTION OUTPUT TRISTATE ;
    USE SIGNAL ;
    ANTENNADIFFAREA 0.795200 ;
    PORT
      LAYER met2 ;
        RECT 454.110 0.000 454.390 4.000 ;
    END
  END mem_wdata[0]
  PIN mem_wdata[10]
    DIRECTION OUTPUT TRISTATE ;
    USE SIGNAL ;
    ANTENNADIFFAREA 0.795200 ;
    PORT
      LAYER met2 ;
        RECT 173.970 465.800 174.250 469.800 ;
    END
  END mem_wdata[10]
  PIN mem_wdata[11]
    DIRECTION OUTPUT TRISTATE ;
    USE SIGNAL ;
    ANTENNADIFFAREA 0.795200 ;
    PORT
      LAYER met3 ;
        RECT 0.000 139.440 4.000 140.040 ;
    END
  END mem_wdata[11]
  PIN mem_wdata[12]
    DIRECTION OUTPUT TRISTATE ;
    USE SIGNAL ;
    ANTENNADIFFAREA 0.795200 ;
    PORT
      LAYER met2 ;
        RECT 48.390 465.800 48.670 469.800 ;
    END
  END mem_wdata[12]
  PIN mem_wdata[13]
    DIRECTION OUTPUT TRISTATE ;
    USE SIGNAL ;
    ANTENNADIFFAREA 0.795200 ;
    PORT
      LAYER met3 ;
        RECT 0.000 71.440 4.000 72.040 ;
    END
  END mem_wdata[13]
  PIN mem_wdata[14]
    DIRECTION OUTPUT TRISTATE ;
    USE SIGNAL ;
    ANTENNADIFFAREA 0.795200 ;
    PORT
      LAYER met3 ;
        RECT 455.080 380.840 459.080 381.440 ;
    END
  END mem_wdata[14]
  PIN mem_wdata[15]
    DIRECTION OUTPUT TRISTATE ;
    USE SIGNAL ;
    ANTENNADIFFAREA 0.795200 ;
    PORT
      LAYER met2 ;
        RECT 25.850 0.000 26.130 4.000 ;
    END
  END mem_wdata[15]
  PIN mem_wdata[16]
    DIRECTION OUTPUT TRISTATE ;
    USE SIGNAL ;
    ANTENNADIFFAREA 0.795200 ;
    PORT
      LAYER met2 ;
        RECT 183.630 0.000 183.910 4.000 ;
    END
  END mem_wdata[16]
  PIN mem_wdata[17]
    DIRECTION OUTPUT TRISTATE ;
    USE SIGNAL ;
    ANTENNADIFFAREA 0.795200 ;
    PORT
      LAYER met3 ;
        RECT 0.000 302.640 4.000 303.240 ;
    END
  END mem_wdata[17]
  PIN mem_wdata[18]
    DIRECTION OUTPUT TRISTATE ;
    USE SIGNAL ;
    ANTENNADIFFAREA 0.795200 ;
    PORT
      LAYER met2 ;
        RECT 409.030 0.000 409.310 4.000 ;
    END
  END mem_wdata[18]
  PIN mem_wdata[19]
    DIRECTION OUTPUT TRISTATE ;
    USE SIGNAL ;
    ANTENNADIFFAREA 0.795200 ;
    PORT
      LAYER met3 ;
        RECT 0.000 343.440 4.000 344.040 ;
    END
  END mem_wdata[19]
  PIN mem_wdata[1]
    DIRECTION OUTPUT TRISTATE ;
    USE SIGNAL ;
    ANTENNADIFFAREA 0.795200 ;
    PORT
      LAYER met2 ;
        RECT 289.890 465.800 290.170 469.800 ;
    END
  END mem_wdata[1]
  PIN mem_wdata[20]
    DIRECTION OUTPUT TRISTATE ;
    USE SIGNAL ;
    ANTENNADIFFAREA 0.795200 ;
    PORT
      LAYER met2 ;
        RECT 402.590 0.000 402.870 4.000 ;
    END
  END mem_wdata[20]
  PIN mem_wdata[21]
    DIRECTION OUTPUT TRISTATE ;
    USE SIGNAL ;
    ANTENNADIFFAREA 0.795200 ;
    PORT
      LAYER met2 ;
        RECT 273.790 465.800 274.070 469.800 ;
    END
  END mem_wdata[21]
  PIN mem_wdata[22]
    DIRECTION OUTPUT TRISTATE ;
    USE SIGNAL ;
    ANTENNADIFFAREA 0.445500 ;
    PORT
      LAYER met3 ;
        RECT 455.080 40.840 459.080 41.440 ;
    END
  END mem_wdata[22]
  PIN mem_wdata[23]
    DIRECTION OUTPUT TRISTATE ;
    USE SIGNAL ;
    ANTENNADIFFAREA 0.795200 ;
    PORT
      LAYER met3 ;
        RECT 0.000 176.840 4.000 177.440 ;
    END
  END mem_wdata[23]
  PIN mem_wdata[24]
    DIRECTION OUTPUT TRISTATE ;
    USE SIGNAL ;
    ANTENNADIFFAREA 0.795200 ;
    PORT
      LAYER met3 ;
        RECT 0.000 180.240 4.000 180.840 ;
    END
  END mem_wdata[24]
  PIN mem_wdata[25]
    DIRECTION OUTPUT TRISTATE ;
    USE SIGNAL ;
    ANTENNADIFFAREA 0.795200 ;
    PORT
      LAYER met3 ;
        RECT 0.000 401.240 4.000 401.840 ;
    END
  END mem_wdata[25]
  PIN mem_wdata[26]
    DIRECTION OUTPUT TRISTATE ;
    USE SIGNAL ;
    ANTENNADIFFAREA 0.795200 ;
    PORT
      LAYER met3 ;
        RECT 455.080 306.040 459.080 306.640 ;
    END
  END mem_wdata[26]
  PIN mem_wdata[27]
    DIRECTION OUTPUT TRISTATE ;
    USE SIGNAL ;
    ANTENNADIFFAREA 0.795200 ;
    PORT
      LAYER met2 ;
        RECT 209.390 465.800 209.670 469.800 ;
    END
  END mem_wdata[27]
  PIN mem_wdata[28]
    DIRECTION OUTPUT TRISTATE ;
    USE SIGNAL ;
    ANTENNADIFFAREA 0.795200 ;
    PORT
      LAYER met3 ;
        RECT 0.000 408.040 4.000 408.640 ;
    END
  END mem_wdata[28]
  PIN mem_wdata[29]
    DIRECTION OUTPUT TRISTATE ;
    USE SIGNAL ;
    ANTENNADIFFAREA 0.795200 ;
    PORT
      LAYER met2 ;
        RECT 363.950 465.800 364.230 469.800 ;
    END
  END mem_wdata[29]
  PIN mem_wdata[2]
    DIRECTION OUTPUT TRISTATE ;
    USE SIGNAL ;
    ANTENNADIFFAREA 0.795200 ;
    PORT
      LAYER met3 ;
        RECT 0.000 452.240 4.000 452.840 ;
    END
  END mem_wdata[2]
  PIN mem_wdata[30]
    DIRECTION OUTPUT TRISTATE ;
    USE SIGNAL ;
    ANTENNADIFFAREA 0.795200 ;
    PORT
      LAYER met3 ;
        RECT 0.000 326.440 4.000 327.040 ;
    END
  END mem_wdata[30]
  PIN mem_wdata[31]
    DIRECTION OUTPUT TRISTATE ;
    USE SIGNAL ;
    ANTENNADIFFAREA 0.795200 ;
    PORT
      LAYER met3 ;
        RECT 0.000 387.640 4.000 388.240 ;
    END
  END mem_wdata[31]
  PIN mem_wdata[3]
    DIRECTION OUTPUT TRISTATE ;
    USE SIGNAL ;
    ANTENNADIFFAREA 0.795200 ;
    PORT
      LAYER met3 ;
        RECT 0.000 241.440 4.000 242.040 ;
    END
  END mem_wdata[3]
  PIN mem_wdata[4]
    DIRECTION OUTPUT TRISTATE ;
    USE SIGNAL ;
    ANTENNADIFFAREA 0.795200 ;
    PORT
      LAYER met2 ;
        RECT 119.230 0.000 119.510 4.000 ;
    END
  END mem_wdata[4]
  PIN mem_wdata[5]
    DIRECTION OUTPUT TRISTATE ;
    USE SIGNAL ;
    ANTENNADIFFAREA 0.795200 ;
    PORT
      LAYER met2 ;
        RECT 386.490 0.000 386.770 4.000 ;
    END
  END mem_wdata[5]
  PIN mem_wdata[6]
    DIRECTION OUTPUT TRISTATE ;
    USE SIGNAL ;
    ANTENNADIFFAREA 0.445500 ;
    PORT
      LAYER met3 ;
        RECT 455.080 20.440 459.080 21.040 ;
    END
  END mem_wdata[6]
  PIN mem_wdata[7]
    DIRECTION OUTPUT TRISTATE ;
    USE SIGNAL ;
    ANTENNADIFFAREA 0.795200 ;
    PORT
      LAYER met3 ;
        RECT 0.000 333.240 4.000 333.840 ;
    END
  END mem_wdata[7]
  PIN mem_wdata[8]
    DIRECTION OUTPUT TRISTATE ;
    USE SIGNAL ;
    ANTENNADIFFAREA 0.445500 ;
    PORT
      LAYER met2 ;
        RECT 450.890 465.800 451.170 469.800 ;
    END
  END mem_wdata[8]
  PIN mem_wdata[9]
    DIRECTION OUTPUT TRISTATE ;
    USE SIGNAL ;
    ANTENNADIFFAREA 0.795200 ;
    PORT
      LAYER met2 ;
        RECT 280.230 0.000 280.510 4.000 ;
    END
  END mem_wdata[9]
  PIN mem_wstrb[0]
    DIRECTION OUTPUT TRISTATE ;
    USE SIGNAL ;
    ANTENNADIFFAREA 0.795200 ;
    PORT
      LAYER met3 ;
        RECT 455.080 207.440 459.080 208.040 ;
    END
  END mem_wstrb[0]
  PIN mem_wstrb[1]
    DIRECTION OUTPUT TRISTATE ;
    USE SIGNAL ;
    ANTENNADIFFAREA 0.795200 ;
    PORT
      LAYER met3 ;
        RECT 455.080 159.840 459.080 160.440 ;
    END
  END mem_wstrb[1]
  PIN mem_wstrb[2]
    DIRECTION OUTPUT TRISTATE ;
    USE SIGNAL ;
    ANTENNADIFFAREA 0.445500 ;
    PORT
      LAYER met3 ;
        RECT 455.080 316.240 459.080 316.840 ;
    END
  END mem_wstrb[2]
  PIN mem_wstrb[3]
    DIRECTION OUTPUT TRISTATE ;
    USE SIGNAL ;
    ANTENNADIFFAREA 0.445500 ;
    PORT
      LAYER met3 ;
        RECT 455.080 251.640 459.080 252.240 ;
    END
  END mem_wstrb[3]
  PIN pcpi_insn[0]
    DIRECTION OUTPUT TRISTATE ;
    USE SIGNAL ;
    PORT
      LAYER met2 ;
        RECT 19.410 465.800 19.690 469.800 ;
    END
  END pcpi_insn[0]
  PIN pcpi_insn[10]
    DIRECTION OUTPUT TRISTATE ;
    USE SIGNAL ;
    PORT
      LAYER met3 ;
        RECT 455.080 258.440 459.080 259.040 ;
    END
  END pcpi_insn[10]
  PIN pcpi_insn[11]
    DIRECTION OUTPUT TRISTATE ;
    USE SIGNAL ;
    PORT
      LAYER met3 ;
        RECT 0.000 17.040 4.000 17.640 ;
    END
  END pcpi_insn[11]
  PIN pcpi_insn[12]
    DIRECTION OUTPUT TRISTATE ;
    USE SIGNAL ;
    PORT
      LAYER met2 ;
        RECT 392.930 0.000 393.210 4.000 ;
    END
  END pcpi_insn[12]
  PIN pcpi_insn[13]
    DIRECTION OUTPUT TRISTATE ;
    USE SIGNAL ;
    PORT
      LAYER met2 ;
        RECT 64.490 0.000 64.770 4.000 ;
    END
  END pcpi_insn[13]
  PIN pcpi_insn[14]
    DIRECTION OUTPUT TRISTATE ;
    USE SIGNAL ;
    PORT
      LAYER met3 ;
        RECT 0.000 57.840 4.000 58.440 ;
    END
  END pcpi_insn[14]
  PIN pcpi_insn[15]
    DIRECTION OUTPUT TRISTATE ;
    USE SIGNAL ;
    PORT
      LAYER met2 ;
        RECT 45.170 465.800 45.450 469.800 ;
    END
  END pcpi_insn[15]
  PIN pcpi_insn[16]
    DIRECTION OUTPUT TRISTATE ;
    USE SIGNAL ;
    PORT
      LAYER met3 ;
        RECT 455.080 27.240 459.080 27.840 ;
    END
  END pcpi_insn[16]
  PIN pcpi_insn[17]
    DIRECTION OUTPUT TRISTATE ;
    USE SIGNAL ;
    PORT
      LAYER met3 ;
        RECT 0.000 316.240 4.000 316.840 ;
    END
  END pcpi_insn[17]
  PIN pcpi_insn[18]
    DIRECTION OUTPUT TRISTATE ;
    USE SIGNAL ;
    PORT
      LAYER met2 ;
        RECT 434.790 465.800 435.070 469.800 ;
    END
  END pcpi_insn[18]
  PIN pcpi_insn[19]
    DIRECTION OUTPUT TRISTATE ;
    USE SIGNAL ;
    PORT
      LAYER met2 ;
        RECT 202.950 465.800 203.230 469.800 ;
    END
  END pcpi_insn[19]
  PIN pcpi_insn[1]
    DIRECTION OUTPUT TRISTATE ;
    USE SIGNAL ;
    PORT
      LAYER met2 ;
        RECT 354.290 465.800 354.570 469.800 ;
    END
  END pcpi_insn[1]
  PIN pcpi_insn[20]
    DIRECTION OUTPUT TRISTATE ;
    USE SIGNAL ;
    PORT
      LAYER met2 ;
        RECT 125.670 0.000 125.950 4.000 ;
    END
  END pcpi_insn[20]
  PIN pcpi_insn[21]
    DIRECTION OUTPUT TRISTATE ;
    USE SIGNAL ;
    PORT
      LAYER met3 ;
        RECT 0.000 268.640 4.000 269.240 ;
    END
  END pcpi_insn[21]
  PIN pcpi_insn[22]
    DIRECTION OUTPUT TRISTATE ;
    USE SIGNAL ;
    PORT
      LAYER met2 ;
        RECT 396.150 0.000 396.430 4.000 ;
    END
  END pcpi_insn[22]
  PIN pcpi_insn[23]
    DIRECTION OUTPUT TRISTATE ;
    USE SIGNAL ;
    PORT
      LAYER met2 ;
        RECT 325.310 465.800 325.590 469.800 ;
    END
  END pcpi_insn[23]
  PIN pcpi_insn[24]
    DIRECTION OUTPUT TRISTATE ;
    USE SIGNAL ;
    PORT
      LAYER met2 ;
        RECT 77.370 0.000 77.650 4.000 ;
    END
  END pcpi_insn[24]
  PIN pcpi_insn[25]
    DIRECTION OUTPUT TRISTATE ;
    USE SIGNAL ;
    PORT
      LAYER met3 ;
        RECT 0.000 295.840 4.000 296.440 ;
    END
  END pcpi_insn[25]
  PIN pcpi_insn[26]
    DIRECTION OUTPUT TRISTATE ;
    USE SIGNAL ;
    PORT
      LAYER met3 ;
        RECT 455.080 438.640 459.080 439.240 ;
    END
  END pcpi_insn[26]
  PIN pcpi_insn[27]
    DIRECTION OUTPUT TRISTATE ;
    USE SIGNAL ;
    PORT
      LAYER met3 ;
        RECT 455.080 459.040 459.080 459.640 ;
    END
  END pcpi_insn[27]
  PIN pcpi_insn[28]
    DIRECTION OUTPUT TRISTATE ;
    USE SIGNAL ;
    PORT
      LAYER met3 ;
        RECT 455.080 391.040 459.080 391.640 ;
    END
  END pcpi_insn[28]
  PIN pcpi_insn[29]
    DIRECTION OUTPUT TRISTATE ;
    USE SIGNAL ;
    PORT
      LAYER met2 ;
        RECT 212.610 465.800 212.890 469.800 ;
    END
  END pcpi_insn[29]
  PIN pcpi_insn[2]
    DIRECTION OUTPUT TRISTATE ;
    USE SIGNAL ;
    PORT
      LAYER met3 ;
        RECT 455.080 370.640 459.080 371.240 ;
    END
  END pcpi_insn[2]
  PIN pcpi_insn[30]
    DIRECTION OUTPUT TRISTATE ;
    USE SIGNAL ;
    PORT
      LAYER met2 ;
        RECT 228.710 0.000 228.990 4.000 ;
    END
  END pcpi_insn[30]
  PIN pcpi_insn[31]
    DIRECTION OUTPUT TRISTATE ;
    USE SIGNAL ;
    PORT
      LAYER met2 ;
        RECT 415.470 465.800 415.750 469.800 ;
    END
  END pcpi_insn[31]
  PIN pcpi_insn[3]
    DIRECTION OUTPUT TRISTATE ;
    USE SIGNAL ;
    PORT
      LAYER met2 ;
        RECT 12.970 0.000 13.250 4.000 ;
    END
  END pcpi_insn[3]
  PIN pcpi_insn[4]
    DIRECTION OUTPUT TRISTATE ;
    USE SIGNAL ;
    PORT
      LAYER met2 ;
        RECT 3.310 0.000 3.590 4.000 ;
    END
  END pcpi_insn[4]
  PIN pcpi_insn[5]
    DIRECTION OUTPUT TRISTATE ;
    USE SIGNAL ;
    PORT
      LAYER met2 ;
        RECT 77.370 465.800 77.650 469.800 ;
    END
  END pcpi_insn[5]
  PIN pcpi_insn[6]
    DIRECTION OUTPUT TRISTATE ;
    USE SIGNAL ;
    PORT
      LAYER met2 ;
        RECT 231.930 0.000 232.210 4.000 ;
    END
  END pcpi_insn[6]
  PIN pcpi_insn[7]
    DIRECTION OUTPUT TRISTATE ;
    USE SIGNAL ;
    PORT
      LAYER met3 ;
        RECT 455.080 3.440 459.080 4.040 ;
    END
  END pcpi_insn[7]
  PIN pcpi_insn[8]
    DIRECTION OUTPUT TRISTATE ;
    USE SIGNAL ;
    PORT
      LAYER met2 ;
        RECT 447.670 465.800 447.950 469.800 ;
    END
  END pcpi_insn[8]
  PIN pcpi_insn[9]
    DIRECTION OUTPUT TRISTATE ;
    USE SIGNAL ;
    PORT
      LAYER met3 ;
        RECT 0.000 153.040 4.000 153.640 ;
    END
  END pcpi_insn[9]
  PIN pcpi_rd[0]
    DIRECTION INPUT ;
    USE SIGNAL ;
    PORT
      LAYER met2 ;
        RECT 183.630 465.800 183.910 469.800 ;
    END
  END pcpi_rd[0]
  PIN pcpi_rd[10]
    DIRECTION INPUT ;
    USE SIGNAL ;
    PORT
      LAYER met3 ;
        RECT 0.000 306.040 4.000 306.640 ;
    END
  END pcpi_rd[10]
  PIN pcpi_rd[11]
    DIRECTION INPUT ;
    USE SIGNAL ;
    PORT
      LAYER met2 ;
        RECT 87.030 0.000 87.310 4.000 ;
    END
  END pcpi_rd[11]
  PIN pcpi_rd[12]
    DIRECTION INPUT ;
    USE SIGNAL ;
    PORT
      LAYER met2 ;
        RECT 196.510 0.000 196.790 4.000 ;
    END
  END pcpi_rd[12]
  PIN pcpi_rd[13]
    DIRECTION INPUT ;
    USE SIGNAL ;
    PORT
      LAYER met2 ;
        RECT 389.710 465.800 389.990 469.800 ;
    END
  END pcpi_rd[13]
  PIN pcpi_rd[14]
    DIRECTION INPUT ;
    USE SIGNAL ;
    PORT
      LAYER met3 ;
        RECT 0.000 125.840 4.000 126.440 ;
    END
  END pcpi_rd[14]
  PIN pcpi_rd[15]
    DIRECTION INPUT ;
    USE SIGNAL ;
    PORT
      LAYER met3 ;
        RECT 0.000 54.440 4.000 55.040 ;
    END
  END pcpi_rd[15]
  PIN pcpi_rd[16]
    DIRECTION INPUT ;
    USE SIGNAL ;
    PORT
      LAYER met2 ;
        RECT 334.970 0.000 335.250 4.000 ;
    END
  END pcpi_rd[16]
  PIN pcpi_rd[17]
    DIRECTION INPUT ;
    USE SIGNAL ;
    PORT
      LAYER met3 ;
        RECT 455.080 217.640 459.080 218.240 ;
    END
  END pcpi_rd[17]
  PIN pcpi_rd[18]
    DIRECTION INPUT ;
    USE SIGNAL ;
    PORT
      LAYER met3 ;
        RECT 455.080 302.640 459.080 303.240 ;
    END
  END pcpi_rd[18]
  PIN pcpi_rd[19]
    DIRECTION INPUT ;
    USE SIGNAL ;
    PORT
      LAYER met2 ;
        RECT 344.630 0.000 344.910 4.000 ;
    END
  END pcpi_rd[19]
  PIN pcpi_rd[1]
    DIRECTION INPUT ;
    USE SIGNAL ;
    PORT
      LAYER met2 ;
        RECT 161.090 465.800 161.370 469.800 ;
    END
  END pcpi_rd[1]
  PIN pcpi_rd[20]
    DIRECTION INPUT ;
    USE SIGNAL ;
    PORT
      LAYER met2 ;
        RECT 441.230 0.000 441.510 4.000 ;
    END
  END pcpi_rd[20]
  PIN pcpi_rd[21]
    DIRECTION INPUT ;
    USE SIGNAL ;
    PORT
      LAYER met3 ;
        RECT 455.080 289.040 459.080 289.640 ;
    END
  END pcpi_rd[21]
  PIN pcpi_rd[22]
    DIRECTION INPUT ;
    USE SIGNAL ;
    PORT
      LAYER met3 ;
        RECT 0.000 289.040 4.000 289.640 ;
    END
  END pcpi_rd[22]
  PIN pcpi_rd[23]
    DIRECTION INPUT ;
    USE SIGNAL ;
    PORT
      LAYER met3 ;
        RECT 455.080 231.240 459.080 231.840 ;
    END
  END pcpi_rd[23]
  PIN pcpi_rd[24]
    DIRECTION INPUT ;
    USE SIGNAL ;
    PORT
      LAYER met3 ;
        RECT 0.000 353.640 4.000 354.240 ;
    END
  END pcpi_rd[24]
  PIN pcpi_rd[25]
    DIRECTION INPUT ;
    USE SIGNAL ;
    PORT
      LAYER met2 ;
        RECT 412.250 465.800 412.530 469.800 ;
    END
  END pcpi_rd[25]
  PIN pcpi_rd[26]
    DIRECTION INPUT ;
    USE SIGNAL ;
    PORT
      LAYER met3 ;
        RECT 455.080 34.040 459.080 34.640 ;
    END
  END pcpi_rd[26]
  PIN pcpi_rd[27]
    DIRECTION INPUT ;
    USE SIGNAL ;
    PORT
      LAYER met2 ;
        RECT 283.450 465.800 283.730 469.800 ;
    END
  END pcpi_rd[27]
  PIN pcpi_rd[28]
    DIRECTION INPUT ;
    USE SIGNAL ;
    PORT
      LAYER met2 ;
        RECT 415.470 0.000 415.750 4.000 ;
    END
  END pcpi_rd[28]
  PIN pcpi_rd[29]
    DIRECTION INPUT ;
    USE SIGNAL ;
    PORT
      LAYER met2 ;
        RECT 125.670 465.800 125.950 469.800 ;
    END
  END pcpi_rd[29]
  PIN pcpi_rd[2]
    DIRECTION INPUT ;
    USE SIGNAL ;
    PORT
      LAYER met2 ;
        RECT 54.830 0.000 55.110 4.000 ;
    END
  END pcpi_rd[2]
  PIN pcpi_rd[30]
    DIRECTION INPUT ;
    USE SIGNAL ;
    PORT
      LAYER met3 ;
        RECT 0.000 3.440 4.000 4.040 ;
    END
  END pcpi_rd[30]
  PIN pcpi_rd[31]
    DIRECTION INPUT ;
    USE SIGNAL ;
    PORT
      LAYER met3 ;
        RECT 0.000 462.440 4.000 463.040 ;
    END
  END pcpi_rd[31]
  PIN pcpi_rd[3]
    DIRECTION INPUT ;
    USE SIGNAL ;
    PORT
      LAYER met3 ;
        RECT 455.080 295.840 459.080 296.440 ;
    END
  END pcpi_rd[3]
  PIN pcpi_rd[4]
    DIRECTION INPUT ;
    USE SIGNAL ;
    PORT
      LAYER met2 ;
        RECT 112.790 0.000 113.070 4.000 ;
    END
  END pcpi_rd[4]
  PIN pcpi_rd[5]
    DIRECTION INPUT ;
    USE SIGNAL ;
    PORT
      LAYER met2 ;
        RECT 428.350 0.000 428.630 4.000 ;
    END
  END pcpi_rd[5]
  PIN pcpi_rd[6]
    DIRECTION INPUT ;
    USE SIGNAL ;
    PORT
      LAYER met2 ;
        RECT 148.210 465.800 148.490 469.800 ;
    END
  END pcpi_rd[6]
  PIN pcpi_rd[7]
    DIRECTION INPUT ;
    USE SIGNAL ;
    PORT
      LAYER met2 ;
        RECT 399.370 465.800 399.650 469.800 ;
    END
  END pcpi_rd[7]
  PIN pcpi_rd[8]
    DIRECTION INPUT ;
    USE SIGNAL ;
    PORT
      LAYER met3 ;
        RECT 455.080 346.840 459.080 347.440 ;
    END
  END pcpi_rd[8]
  PIN pcpi_rd[9]
    DIRECTION INPUT ;
    USE SIGNAL ;
    PORT
      LAYER met2 ;
        RECT 128.890 465.800 129.170 469.800 ;
    END
  END pcpi_rd[9]
  PIN pcpi_ready
    DIRECTION INPUT ;
    USE SIGNAL ;
    PORT
      LAYER met3 ;
        RECT 0.000 68.040 4.000 68.640 ;
    END
  END pcpi_ready
  PIN pcpi_rs1[0]
    DIRECTION OUTPUT TRISTATE ;
    USE SIGNAL ;
    ANTENNADIFFAREA 0.445500 ;
    PORT
      LAYER met3 ;
        RECT 455.080 71.440 459.080 72.040 ;
    END
  END pcpi_rs1[0]
  PIN pcpi_rs1[10]
    DIRECTION OUTPUT TRISTATE ;
    USE SIGNAL ;
    ANTENNADIFFAREA 0.445500 ;
    PORT
      LAYER met2 ;
        RECT 99.910 465.800 100.190 469.800 ;
    END
  END pcpi_rs1[10]
  PIN pcpi_rs1[11]
    DIRECTION OUTPUT TRISTATE ;
    USE SIGNAL ;
    ANTENNADIFFAREA 0.795200 ;
    PORT
      LAYER met3 ;
        RECT 455.080 153.040 459.080 153.640 ;
    END
  END pcpi_rs1[11]
  PIN pcpi_rs1[12]
    DIRECTION OUTPUT TRISTATE ;
    USE SIGNAL ;
    ANTENNADIFFAREA 0.795200 ;
    PORT
      LAYER met2 ;
        RECT 315.650 465.800 315.930 469.800 ;
    END
  END pcpi_rs1[12]
  PIN pcpi_rs1[13]
    DIRECTION OUTPUT TRISTATE ;
    USE SIGNAL ;
    ANTENNADIFFAREA 0.795200 ;
    PORT
      LAYER met2 ;
        RECT 219.050 465.800 219.330 469.800 ;
    END
  END pcpi_rs1[13]
  PIN pcpi_rs1[14]
    DIRECTION OUTPUT TRISTATE ;
    USE SIGNAL ;
    ANTENNADIFFAREA 0.795200 ;
    PORT
      LAYER met2 ;
        RECT 41.950 465.800 42.230 469.800 ;
    END
  END pcpi_rs1[14]
  PIN pcpi_rs1[15]
    DIRECTION OUTPUT TRISTATE ;
    USE SIGNAL ;
    ANTENNADIFFAREA 0.795200 ;
    PORT
      LAYER met2 ;
        RECT 38.730 0.000 39.010 4.000 ;
    END
  END pcpi_rs1[15]
  PIN pcpi_rs1[16]
    DIRECTION OUTPUT TRISTATE ;
    USE SIGNAL ;
    ANTENNADIFFAREA 0.795200 ;
    PORT
      LAYER met2 ;
        RECT 251.250 0.000 251.530 4.000 ;
    END
  END pcpi_rs1[16]
  PIN pcpi_rs1[17]
    DIRECTION OUTPUT TRISTATE ;
    USE SIGNAL ;
    ANTENNADIFFAREA 0.445500 ;
    PORT
      LAYER met3 ;
        RECT 455.080 340.040 459.080 340.640 ;
    END
  END pcpi_rs1[17]
  PIN pcpi_rs1[18]
    DIRECTION OUTPUT TRISTATE ;
    USE SIGNAL ;
    ANTENNADIFFAREA 0.795200 ;
    PORT
      LAYER met3 ;
        RECT 455.080 309.440 459.080 310.040 ;
    END
  END pcpi_rs1[18]
  PIN pcpi_rs1[19]
    DIRECTION OUTPUT TRISTATE ;
    USE SIGNAL ;
    ANTENNADIFFAREA 0.795200 ;
    PORT
      LAYER met2 ;
        RECT 286.670 0.000 286.950 4.000 ;
    END
  END pcpi_rs1[19]
  PIN pcpi_rs1[1]
    DIRECTION OUTPUT TRISTATE ;
    USE SIGNAL ;
    ANTENNADIFFAREA 0.795200 ;
    PORT
      LAYER met3 ;
        RECT 455.080 272.040 459.080 272.640 ;
    END
  END pcpi_rs1[1]
  PIN pcpi_rs1[20]
    DIRECTION OUTPUT TRISTATE ;
    USE SIGNAL ;
    ANTENNADIFFAREA 0.795200 ;
    PORT
      LAYER met3 ;
        RECT 455.080 139.440 459.080 140.040 ;
    END
  END pcpi_rs1[20]
  PIN pcpi_rs1[21]
    DIRECTION OUTPUT TRISTATE ;
    USE SIGNAL ;
    ANTENNADIFFAREA 0.795200 ;
    PORT
      LAYER met2 ;
        RECT 431.570 0.000 431.850 4.000 ;
    END
  END pcpi_rs1[21]
  PIN pcpi_rs1[22]
    DIRECTION OUTPUT TRISTATE ;
    USE SIGNAL ;
    ANTENNADIFFAREA 0.795200 ;
    PORT
      LAYER met2 ;
        RECT 302.770 465.800 303.050 469.800 ;
    END
  END pcpi_rs1[22]
  PIN pcpi_rs1[23]
    DIRECTION OUTPUT TRISTATE ;
    USE SIGNAL ;
    ANTENNADIFFAREA 0.795200 ;
    PORT
      LAYER met2 ;
        RECT 431.570 465.800 431.850 469.800 ;
    END
  END pcpi_rs1[23]
  PIN pcpi_rs1[24]
    DIRECTION OUTPUT TRISTATE ;
    USE SIGNAL ;
    ANTENNADIFFAREA 0.795200 ;
    PORT
      LAYER met2 ;
        RECT 254.470 0.000 254.750 4.000 ;
    END
  END pcpi_rs1[24]
  PIN pcpi_rs1[25]
    DIRECTION OUTPUT TRISTATE ;
    USE SIGNAL ;
    ANTENNADIFFAREA 0.795200 ;
    PORT
      LAYER met2 ;
        RECT 367.170 0.000 367.450 4.000 ;
    END
  END pcpi_rs1[25]
  PIN pcpi_rs1[26]
    DIRECTION OUTPUT TRISTATE ;
    USE SIGNAL ;
    ANTENNADIFFAREA 0.795200 ;
    PORT
      LAYER met3 ;
        RECT 455.080 95.240 459.080 95.840 ;
    END
  END pcpi_rs1[26]
  PIN pcpi_rs1[27]
    DIRECTION OUTPUT TRISTATE ;
    USE SIGNAL ;
    ANTENNADIFFAREA 0.795200 ;
    PORT
      LAYER met2 ;
        RECT 67.710 465.800 67.990 469.800 ;
    END
  END pcpi_rs1[27]
  PIN pcpi_rs1[28]
    DIRECTION OUTPUT TRISTATE ;
    USE SIGNAL ;
    ANTENNADIFFAREA 0.795200 ;
    PORT
      LAYER met3 ;
        RECT 0.000 81.640 4.000 82.240 ;
    END
  END pcpi_rs1[28]
  PIN pcpi_rs1[29]
    DIRECTION OUTPUT TRISTATE ;
    USE SIGNAL ;
    ANTENNADIFFAREA 0.795200 ;
    PORT
      LAYER met2 ;
        RECT 48.390 0.000 48.670 4.000 ;
    END
  END pcpi_rs1[29]
  PIN pcpi_rs1[2]
    DIRECTION OUTPUT TRISTATE ;
    USE SIGNAL ;
    ANTENNADIFFAREA 0.795200 ;
    PORT
      LAYER met2 ;
        RECT 164.310 465.800 164.590 469.800 ;
    END
  END pcpi_rs1[2]
  PIN pcpi_rs1[30]
    DIRECTION OUTPUT TRISTATE ;
    USE SIGNAL ;
    ANTENNADIFFAREA 0.795200 ;
    PORT
      LAYER met3 ;
        RECT 0.000 170.040 4.000 170.640 ;
    END
  END pcpi_rs1[30]
  PIN pcpi_rs1[31]
    DIRECTION OUTPUT TRISTATE ;
    USE SIGNAL ;
    ANTENNADIFFAREA 0.445500 ;
    PORT
      LAYER met3 ;
        RECT 455.080 445.440 459.080 446.040 ;
    END
  END pcpi_rs1[31]
  PIN pcpi_rs1[3]
    DIRECTION OUTPUT TRISTATE ;
    USE SIGNAL ;
    ANTENNADIFFAREA 0.795200 ;
    PORT
      LAYER met2 ;
        RECT 173.970 0.000 174.250 4.000 ;
    END
  END pcpi_rs1[3]
  PIN pcpi_rs1[4]
    DIRECTION OUTPUT TRISTATE ;
    USE SIGNAL ;
    ANTENNADIFFAREA 0.795200 ;
    PORT
      LAYER met3 ;
        RECT 0.000 190.440 4.000 191.040 ;
    END
  END pcpi_rs1[4]
  PIN pcpi_rs1[5]
    DIRECTION OUTPUT TRISTATE ;
    USE SIGNAL ;
    ANTENNADIFFAREA 0.445500 ;
    PORT
      LAYER met3 ;
        RECT 455.080 190.440 459.080 191.040 ;
    END
  END pcpi_rs1[5]
  PIN pcpi_rs1[6]
    DIRECTION OUTPUT TRISTATE ;
    USE SIGNAL ;
    ANTENNADIFFAREA 0.795200 ;
    PORT
      LAYER met2 ;
        RECT 351.070 0.000 351.350 4.000 ;
    END
  END pcpi_rs1[6]
  PIN pcpi_rs1[7]
    DIRECTION OUTPUT TRISTATE ;
    USE SIGNAL ;
    ANTENNADIFFAREA 0.795200 ;
    PORT
      LAYER met2 ;
        RECT 360.730 465.800 361.010 469.800 ;
    END
  END pcpi_rs1[7]
  PIN pcpi_rs1[8]
    DIRECTION OUTPUT TRISTATE ;
    USE SIGNAL ;
    ANTENNADIFFAREA 0.795200 ;
    PORT
      LAYER met2 ;
        RECT 338.190 0.000 338.470 4.000 ;
    END
  END pcpi_rs1[8]
  PIN pcpi_rs1[9]
    DIRECTION OUTPUT TRISTATE ;
    USE SIGNAL ;
    ANTENNADIFFAREA 0.795200 ;
    PORT
      LAYER met3 ;
        RECT 0.000 231.240 4.000 231.840 ;
    END
  END pcpi_rs1[9]
  PIN pcpi_rs2[0]
    DIRECTION OUTPUT TRISTATE ;
    USE SIGNAL ;
    ANTENNADIFFAREA 0.795200 ;
    PORT
      LAYER met2 ;
        RECT 19.410 0.000 19.690 4.000 ;
    END
  END pcpi_rs2[0]
  PIN pcpi_rs2[10]
    DIRECTION OUTPUT TRISTATE ;
    USE SIGNAL ;
    ANTENNADIFFAREA 0.795200 ;
    PORT
      LAYER met2 ;
        RECT 450.890 0.000 451.170 4.000 ;
    END
  END pcpi_rs2[10]
  PIN pcpi_rs2[11]
    DIRECTION OUTPUT TRISTATE ;
    USE SIGNAL ;
    ANTENNADIFFAREA 0.445500 ;
    PORT
      LAYER met3 ;
        RECT 455.080 119.040 459.080 119.640 ;
    END
  END pcpi_rs2[11]
  PIN pcpi_rs2[12]
    DIRECTION OUTPUT TRISTATE ;
    USE SIGNAL ;
    ANTENNADIFFAREA 0.795200 ;
    PORT
      LAYER met2 ;
        RECT 151.430 465.800 151.710 469.800 ;
    END
  END pcpi_rs2[12]
  PIN pcpi_rs2[13]
    DIRECTION OUTPUT TRISTATE ;
    USE SIGNAL ;
    ANTENNADIFFAREA 0.445500 ;
    PORT
      LAYER met3 ;
        RECT 455.080 404.640 459.080 405.240 ;
    END
  END pcpi_rs2[13]
  PIN pcpi_rs2[14]
    DIRECTION OUTPUT TRISTATE ;
    USE SIGNAL ;
    ANTENNADIFFAREA 0.795200 ;
    PORT
      LAYER met3 ;
        RECT 0.000 370.640 4.000 371.240 ;
    END
  END pcpi_rs2[14]
  PIN pcpi_rs2[15]
    DIRECTION OUTPUT TRISTATE ;
    USE SIGNAL ;
    ANTENNADIFFAREA 0.795200 ;
    PORT
      LAYER met3 ;
        RECT 0.000 404.640 4.000 405.240 ;
    END
  END pcpi_rs2[15]
  PIN pcpi_rs2[16]
    DIRECTION OUTPUT TRISTATE ;
    USE SIGNAL ;
    ANTENNADIFFAREA 0.795200 ;
    PORT
      LAYER met3 ;
        RECT 0.000 391.040 4.000 391.640 ;
    END
  END pcpi_rs2[16]
  PIN pcpi_rs2[17]
    DIRECTION OUTPUT TRISTATE ;
    USE SIGNAL ;
    ANTENNADIFFAREA 0.795200 ;
    PORT
      LAYER met2 ;
        RECT 16.190 0.000 16.470 4.000 ;
    END
  END pcpi_rs2[17]
  PIN pcpi_rs2[18]
    DIRECTION OUTPUT TRISTATE ;
    USE SIGNAL ;
    ANTENNADIFFAREA 0.795200 ;
    PORT
      LAYER met2 ;
        RECT 96.690 0.000 96.970 4.000 ;
    END
  END pcpi_rs2[18]
  PIN pcpi_rs2[19]
    DIRECTION OUTPUT TRISTATE ;
    USE SIGNAL ;
    ANTENNADIFFAREA 0.445500 ;
    PORT
      LAYER met3 ;
        RECT 455.080 234.640 459.080 235.240 ;
    END
  END pcpi_rs2[19]
  PIN pcpi_rs2[1]
    DIRECTION OUTPUT TRISTATE ;
    USE SIGNAL ;
    ANTENNADIFFAREA 0.795200 ;
    PORT
      LAYER met2 ;
        RECT 260.910 0.000 261.190 4.000 ;
    END
  END pcpi_rs2[1]
  PIN pcpi_rs2[20]
    DIRECTION OUTPUT TRISTATE ;
    USE SIGNAL ;
    ANTENNADIFFAREA 0.795200 ;
    PORT
      LAYER met3 ;
        RECT 0.000 78.240 4.000 78.840 ;
    END
  END pcpi_rs2[20]
  PIN pcpi_rs2[21]
    DIRECTION OUTPUT TRISTATE ;
    USE SIGNAL ;
    ANTENNADIFFAREA 0.795200 ;
    PORT
      LAYER met2 ;
        RECT 425.130 465.800 425.410 469.800 ;
    END
  END pcpi_rs2[21]
  PIN pcpi_rs2[22]
    DIRECTION OUTPUT TRISTATE ;
    USE SIGNAL ;
    ANTENNADIFFAREA 0.795200 ;
    PORT
      LAYER met2 ;
        RECT 35.510 465.800 35.790 469.800 ;
    END
  END pcpi_rs2[22]
  PIN pcpi_rs2[23]
    DIRECTION OUTPUT TRISTATE ;
    USE SIGNAL ;
    ANTENNADIFFAREA 0.795200 ;
    PORT
      LAYER met2 ;
        RECT 67.710 0.000 67.990 4.000 ;
    END
  END pcpi_rs2[23]
  PIN pcpi_rs2[24]
    DIRECTION OUTPUT TRISTATE ;
    USE SIGNAL ;
    ANTENNADIFFAREA 0.795200 ;
    PORT
      LAYER met3 ;
        RECT 0.000 119.040 4.000 119.640 ;
    END
  END pcpi_rs2[24]
  PIN pcpi_rs2[25]
    DIRECTION OUTPUT TRISTATE ;
    USE SIGNAL ;
    ANTENNADIFFAREA 0.795200 ;
    PORT
      LAYER met2 ;
        RECT 438.010 465.800 438.290 469.800 ;
    END
  END pcpi_rs2[25]
  PIN pcpi_rs2[26]
    DIRECTION OUTPUT TRISTATE ;
    USE SIGNAL ;
    ANTENNADIFFAREA 0.795200 ;
    PORT
      LAYER met3 ;
        RECT 0.000 282.240 4.000 282.840 ;
    END
  END pcpi_rs2[26]
  PIN pcpi_rs2[27]
    DIRECTION OUTPUT TRISTATE ;
    USE SIGNAL ;
    ANTENNADIFFAREA 0.445500 ;
    PORT
      LAYER met3 ;
        RECT 455.080 363.840 459.080 364.440 ;
    END
  END pcpi_rs2[27]
  PIN pcpi_rs2[28]
    DIRECTION OUTPUT TRISTATE ;
    USE SIGNAL ;
    ANTENNADIFFAREA 0.445500 ;
    PORT
      LAYER met3 ;
        RECT 455.080 146.240 459.080 146.840 ;
    END
  END pcpi_rs2[28]
  PIN pcpi_rs2[29]
    DIRECTION OUTPUT TRISTATE ;
    USE SIGNAL ;
    ANTENNADIFFAREA 0.795200 ;
    PORT
      LAYER met2 ;
        RECT 312.430 0.000 312.710 4.000 ;
    END
  END pcpi_rs2[29]
  PIN pcpi_rs2[2]
    DIRECTION OUTPUT TRISTATE ;
    USE SIGNAL ;
    ANTENNADIFFAREA 0.795200 ;
    PORT
      LAYER met2 ;
        RECT 386.490 465.800 386.770 469.800 ;
    END
  END pcpi_rs2[2]
  PIN pcpi_rs2[30]
    DIRECTION OUTPUT TRISTATE ;
    USE SIGNAL ;
    ANTENNADIFFAREA 0.795200 ;
    PORT
      LAYER met2 ;
        RECT 119.230 465.800 119.510 469.800 ;
    END
  END pcpi_rs2[30]
  PIN pcpi_rs2[31]
    DIRECTION OUTPUT TRISTATE ;
    USE SIGNAL ;
    ANTENNADIFFAREA 0.795200 ;
    PORT
      LAYER met2 ;
        RECT 138.550 0.000 138.830 4.000 ;
    END
  END pcpi_rs2[31]
  PIN pcpi_rs2[3]
    DIRECTION OUTPUT TRISTATE ;
    USE SIGNAL ;
    ANTENNADIFFAREA 0.795200 ;
    PORT
      LAYER met3 ;
        RECT 455.080 278.840 459.080 279.440 ;
    END
  END pcpi_rs2[3]
  PIN pcpi_rs2[4]
    DIRECTION OUTPUT TRISTATE ;
    USE SIGNAL ;
    ANTENNADIFFAREA 0.795200 ;
    PORT
      LAYER met2 ;
        RECT 370.390 0.000 370.670 4.000 ;
    END
  END pcpi_rs2[4]
  PIN pcpi_rs2[5]
    DIRECTION OUTPUT TRISTATE ;
    USE SIGNAL ;
    ANTENNADIFFAREA 0.795200 ;
    PORT
      LAYER met3 ;
        RECT 455.080 129.240 459.080 129.840 ;
    END
  END pcpi_rs2[5]
  PIN pcpi_rs2[6]
    DIRECTION OUTPUT TRISTATE ;
    USE SIGNAL ;
    ANTENNADIFFAREA 0.795200 ;
    PORT
      LAYER met3 ;
        RECT 0.000 255.040 4.000 255.640 ;
    END
  END pcpi_rs2[6]
  PIN pcpi_rs2[7]
    DIRECTION OUTPUT TRISTATE ;
    USE SIGNAL ;
    ANTENNADIFFAREA 0.795200 ;
    PORT
      LAYER met3 ;
        RECT 455.080 6.840 459.080 7.440 ;
    END
  END pcpi_rs2[7]
  PIN pcpi_rs2[8]
    DIRECTION OUTPUT TRISTATE ;
    USE SIGNAL ;
    ANTENNADIFFAREA 0.795200 ;
    PORT
      LAYER met2 ;
        RECT 74.150 0.000 74.430 4.000 ;
    END
  END pcpi_rs2[8]
  PIN pcpi_rs2[9]
    DIRECTION OUTPUT TRISTATE ;
    USE SIGNAL ;
    ANTENNADIFFAREA 0.795200 ;
    PORT
      LAYER met2 ;
        RECT 225.490 0.000 225.770 4.000 ;
    END
  END pcpi_rs2[9]
  PIN pcpi_valid
    DIRECTION OUTPUT TRISTATE ;
    USE SIGNAL ;
    PORT
      LAYER met3 ;
        RECT 455.080 197.240 459.080 197.840 ;
    END
  END pcpi_valid
  PIN pcpi_wait
    DIRECTION INPUT ;
    USE SIGNAL ;
    PORT
      LAYER met2 ;
        RECT 367.170 465.800 367.450 469.800 ;
    END
  END pcpi_wait
  PIN pcpi_wr
    DIRECTION INPUT ;
    USE SIGNAL ;
    PORT
      LAYER met3 ;
        RECT 455.080 418.240 459.080 418.840 ;
    END
  END pcpi_wr
  PIN resetn
    DIRECTION INPUT ;
    USE SIGNAL ;
    ANTENNAGATEAREA 0.742500 ;
    PORT
      LAYER met3 ;
        RECT 455.080 17.040 459.080 17.640 ;
    END
  END resetn
  PIN trace_data[0]
    DIRECTION OUTPUT TRISTATE ;
    USE SIGNAL ;
    PORT
      LAYER met3 ;
        RECT 0.000 95.240 4.000 95.840 ;
    END
  END trace_data[0]
  PIN trace_data[10]
    DIRECTION OUTPUT TRISTATE ;
    USE SIGNAL ;
    PORT
      LAYER met3 ;
        RECT 455.080 265.240 459.080 265.840 ;
    END
  END trace_data[10]
  PIN trace_data[11]
    DIRECTION OUTPUT TRISTATE ;
    USE SIGNAL ;
    PORT
      LAYER met2 ;
        RECT 6.530 0.000 6.810 4.000 ;
    END
  END trace_data[11]
  PIN trace_data[12]
    DIRECTION OUTPUT TRISTATE ;
    USE SIGNAL ;
    PORT
      LAYER met3 ;
        RECT 455.080 428.440 459.080 429.040 ;
    END
  END trace_data[12]
  PIN trace_data[13]
    DIRECTION OUTPUT TRISTATE ;
    USE SIGNAL ;
    PORT
      LAYER met2 ;
        RECT 351.070 465.800 351.350 469.800 ;
    END
  END trace_data[13]
  PIN trace_data[14]
    DIRECTION OUTPUT TRISTATE ;
    USE SIGNAL ;
    PORT
      LAYER met3 ;
        RECT 455.080 44.240 459.080 44.840 ;
    END
  END trace_data[14]
  PIN trace_data[15]
    DIRECTION OUTPUT TRISTATE ;
    USE SIGNAL ;
    PORT
      LAYER met2 ;
        RECT 331.750 465.800 332.030 469.800 ;
    END
  END trace_data[15]
  PIN trace_data[16]
    DIRECTION OUTPUT TRISTATE ;
    USE SIGNAL ;
    PORT
      LAYER met3 ;
        RECT 0.000 132.640 4.000 133.240 ;
    END
  END trace_data[16]
  PIN trace_data[17]
    DIRECTION OUTPUT TRISTATE ;
    USE SIGNAL ;
    PORT
      LAYER met3 ;
        RECT 0.000 146.240 4.000 146.840 ;
    END
  END trace_data[17]
  PIN trace_data[18]
    DIRECTION OUTPUT TRISTATE ;
    USE SIGNAL ;
    PORT
      LAYER met2 ;
        RECT 302.770 0.000 303.050 4.000 ;
    END
  END trace_data[18]
  PIN trace_data[19]
    DIRECTION OUTPUT TRISTATE ;
    USE SIGNAL ;
    PORT
      LAYER met2 ;
        RECT 0.090 0.000 0.370 4.000 ;
    END
  END trace_data[19]
  PIN trace_data[1]
    DIRECTION OUTPUT TRISTATE ;
    USE SIGNAL ;
    PORT
      LAYER met2 ;
        RECT 357.510 0.000 357.790 4.000 ;
    END
  END trace_data[1]
  PIN trace_data[20]
    DIRECTION OUTPUT TRISTATE ;
    USE SIGNAL ;
    PORT
      LAYER met3 ;
        RECT 0.000 227.840 4.000 228.440 ;
    END
  END trace_data[20]
  PIN trace_data[21]
    DIRECTION OUTPUT TRISTATE ;
    USE SIGNAL ;
    PORT
      LAYER met3 ;
        RECT 0.000 414.840 4.000 415.440 ;
    END
  END trace_data[21]
  PIN trace_data[22]
    DIRECTION OUTPUT TRISTATE ;
    USE SIGNAL ;
    PORT
      LAYER met2 ;
        RECT 135.330 465.800 135.610 469.800 ;
    END
  END trace_data[22]
  PIN trace_data[23]
    DIRECTION OUTPUT TRISTATE ;
    USE SIGNAL ;
    PORT
      LAYER met3 ;
        RECT 0.000 156.440 4.000 157.040 ;
    END
  END trace_data[23]
  PIN trace_data[24]
    DIRECTION OUTPUT TRISTATE ;
    USE SIGNAL ;
    PORT
      LAYER met2 ;
        RECT 90.250 0.000 90.530 4.000 ;
    END
  END trace_data[24]
  PIN trace_data[25]
    DIRECTION OUTPUT TRISTATE ;
    USE SIGNAL ;
    PORT
      LAYER met2 ;
        RECT 32.290 0.000 32.570 4.000 ;
    END
  END trace_data[25]
  PIN trace_data[26]
    DIRECTION OUTPUT TRISTATE ;
    USE SIGNAL ;
    PORT
      LAYER met2 ;
        RECT 244.810 465.800 245.090 469.800 ;
    END
  END trace_data[26]
  PIN trace_data[27]
    DIRECTION OUTPUT TRISTATE ;
    USE SIGNAL ;
    PORT
      LAYER met2 ;
        RECT 141.770 465.800 142.050 469.800 ;
    END
  END trace_data[27]
  PIN trace_data[28]
    DIRECTION OUTPUT TRISTATE ;
    USE SIGNAL ;
    PORT
      LAYER met2 ;
        RECT 244.810 0.000 245.090 4.000 ;
    END
  END trace_data[28]
  PIN trace_data[29]
    DIRECTION OUTPUT TRISTATE ;
    USE SIGNAL ;
    PORT
      LAYER met2 ;
        RECT 318.870 465.800 319.150 469.800 ;
    END
  END trace_data[29]
  PIN trace_data[2]
    DIRECTION OUTPUT TRISTATE ;
    USE SIGNAL ;
    PORT
      LAYER met3 ;
        RECT 455.080 125.840 459.080 126.440 ;
    END
  END trace_data[2]
  PIN trace_data[30]
    DIRECTION OUTPUT TRISTATE ;
    USE SIGNAL ;
    PORT
      LAYER met3 ;
        RECT 0.000 312.840 4.000 313.440 ;
    END
  END trace_data[30]
  PIN trace_data[31]
    DIRECTION OUTPUT TRISTATE ;
    USE SIGNAL ;
    PORT
      LAYER met3 ;
        RECT 455.080 357.040 459.080 357.640 ;
    END
  END trace_data[31]
  PIN trace_data[32]
    DIRECTION OUTPUT TRISTATE ;
    USE SIGNAL ;
    PORT
      LAYER met2 ;
        RECT 99.910 0.000 100.190 4.000 ;
    END
  END trace_data[32]
  PIN trace_data[33]
    DIRECTION OUTPUT TRISTATE ;
    USE SIGNAL ;
    PORT
      LAYER met2 ;
        RECT 170.750 0.000 171.030 4.000 ;
    END
  END trace_data[33]
  PIN trace_data[34]
    DIRECTION OUTPUT TRISTATE ;
    USE SIGNAL ;
    PORT
      LAYER met3 ;
        RECT 0.000 40.840 4.000 41.440 ;
    END
  END trace_data[34]
  PIN trace_data[35]
    DIRECTION OUTPUT TRISTATE ;
    USE SIGNAL ;
    PORT
      LAYER met3 ;
        RECT 455.080 343.440 459.080 344.040 ;
    END
  END trace_data[35]
  PIN trace_data[3]
    DIRECTION OUTPUT TRISTATE ;
    USE SIGNAL ;
    PORT
      LAYER met2 ;
        RECT 273.790 0.000 274.070 4.000 ;
    END
  END trace_data[3]
  PIN trace_data[4]
    DIRECTION OUTPUT TRISTATE ;
    USE SIGNAL ;
    PORT
      LAYER met2 ;
        RECT 305.990 465.800 306.270 469.800 ;
    END
  END trace_data[4]
  PIN trace_data[5]
    DIRECTION OUTPUT TRISTATE ;
    USE SIGNAL ;
    PORT
      LAYER met2 ;
        RECT 296.330 465.800 296.610 469.800 ;
    END
  END trace_data[5]
  PIN trace_data[6]
    DIRECTION OUTPUT TRISTATE ;
    USE SIGNAL ;
    PORT
      LAYER met3 ;
        RECT 0.000 442.040 4.000 442.640 ;
    END
  END trace_data[6]
  PIN trace_data[7]
    DIRECTION OUTPUT TRISTATE ;
    USE SIGNAL ;
    PORT
      LAYER met2 ;
        RECT 54.830 465.800 55.110 469.800 ;
    END
  END trace_data[7]
  PIN trace_data[8]
    DIRECTION OUTPUT TRISTATE ;
    USE SIGNAL ;
    PORT
      LAYER met2 ;
        RECT 325.310 0.000 325.590 4.000 ;
    END
  END trace_data[8]
  PIN trace_data[9]
    DIRECTION OUTPUT TRISTATE ;
    USE SIGNAL ;
    PORT
      LAYER met3 ;
        RECT 0.000 105.440 4.000 106.040 ;
    END
  END trace_data[9]
  PIN trace_valid
    DIRECTION OUTPUT TRISTATE ;
    USE SIGNAL ;
    PORT
      LAYER met3 ;
        RECT 0.000 394.440 4.000 395.040 ;
    END
  END trace_valid
  PIN trap
    DIRECTION OUTPUT TRISTATE ;
    USE SIGNAL ;
    ANTENNADIFFAREA 0.445500 ;
    PORT
      LAYER met3 ;
        RECT 455.080 227.840 459.080 228.440 ;
    END
  END trap
  OBS
      LAYER li1 ;
        RECT 5.520 10.795 453.560 457.045 ;
      LAYER met1 ;
        RECT 0.070 7.860 459.010 459.980 ;
      LAYER met2 ;
        RECT 0.650 465.520 6.250 466.210 ;
        RECT 7.090 465.520 9.470 466.210 ;
        RECT 10.310 465.520 12.690 466.210 ;
        RECT 13.530 465.520 19.130 466.210 ;
        RECT 19.970 465.520 22.350 466.210 ;
        RECT 23.190 465.520 28.790 466.210 ;
        RECT 29.630 465.520 32.010 466.210 ;
        RECT 32.850 465.520 35.230 466.210 ;
        RECT 36.070 465.520 41.670 466.210 ;
        RECT 42.510 465.520 44.890 466.210 ;
        RECT 45.730 465.520 48.110 466.210 ;
        RECT 48.950 465.520 54.550 466.210 ;
        RECT 55.390 465.520 57.770 466.210 ;
        RECT 58.610 465.520 64.210 466.210 ;
        RECT 65.050 465.520 67.430 466.210 ;
        RECT 68.270 465.520 70.650 466.210 ;
        RECT 71.490 465.520 77.090 466.210 ;
        RECT 77.930 465.520 80.310 466.210 ;
        RECT 81.150 465.520 83.530 466.210 ;
        RECT 84.370 465.520 89.970 466.210 ;
        RECT 90.810 465.520 93.190 466.210 ;
        RECT 94.030 465.520 99.630 466.210 ;
        RECT 100.470 465.520 102.850 466.210 ;
        RECT 103.690 465.520 106.070 466.210 ;
        RECT 106.910 465.520 112.510 466.210 ;
        RECT 113.350 465.520 115.730 466.210 ;
        RECT 116.570 465.520 118.950 466.210 ;
        RECT 119.790 465.520 125.390 466.210 ;
        RECT 126.230 465.520 128.610 466.210 ;
        RECT 129.450 465.520 135.050 466.210 ;
        RECT 135.890 465.520 138.270 466.210 ;
        RECT 139.110 465.520 141.490 466.210 ;
        RECT 142.330 465.520 147.930 466.210 ;
        RECT 148.770 465.520 151.150 466.210 ;
        RECT 151.990 465.520 154.370 466.210 ;
        RECT 155.210 465.520 160.810 466.210 ;
        RECT 161.650 465.520 164.030 466.210 ;
        RECT 164.870 465.520 167.250 466.210 ;
        RECT 168.090 465.520 173.690 466.210 ;
        RECT 174.530 465.520 176.910 466.210 ;
        RECT 177.750 465.520 183.350 466.210 ;
        RECT 184.190 465.520 186.570 466.210 ;
        RECT 187.410 465.520 189.790 466.210 ;
        RECT 190.630 465.520 196.230 466.210 ;
        RECT 197.070 465.520 199.450 466.210 ;
        RECT 200.290 465.520 202.670 466.210 ;
        RECT 203.510 465.520 209.110 466.210 ;
        RECT 209.950 465.520 212.330 466.210 ;
        RECT 213.170 465.520 218.770 466.210 ;
        RECT 219.610 465.520 221.990 466.210 ;
        RECT 222.830 465.520 225.210 466.210 ;
        RECT 226.050 465.520 231.650 466.210 ;
        RECT 232.490 465.520 234.870 466.210 ;
        RECT 235.710 465.520 238.090 466.210 ;
        RECT 238.930 465.520 244.530 466.210 ;
        RECT 245.370 465.520 247.750 466.210 ;
        RECT 248.590 465.520 254.190 466.210 ;
        RECT 255.030 465.520 257.410 466.210 ;
        RECT 258.250 465.520 260.630 466.210 ;
        RECT 261.470 465.520 267.070 466.210 ;
        RECT 267.910 465.520 270.290 466.210 ;
        RECT 271.130 465.520 273.510 466.210 ;
        RECT 274.350 465.520 279.950 466.210 ;
        RECT 280.790 465.520 283.170 466.210 ;
        RECT 284.010 465.520 289.610 466.210 ;
        RECT 290.450 465.520 292.830 466.210 ;
        RECT 293.670 465.520 296.050 466.210 ;
        RECT 296.890 465.520 302.490 466.210 ;
        RECT 303.330 465.520 305.710 466.210 ;
        RECT 306.550 465.520 308.930 466.210 ;
        RECT 309.770 465.520 315.370 466.210 ;
        RECT 316.210 465.520 318.590 466.210 ;
        RECT 319.430 465.520 325.030 466.210 ;
        RECT 325.870 465.520 328.250 466.210 ;
        RECT 329.090 465.520 331.470 466.210 ;
        RECT 332.310 465.520 337.910 466.210 ;
        RECT 338.750 465.520 341.130 466.210 ;
        RECT 341.970 465.520 344.350 466.210 ;
        RECT 345.190 465.520 350.790 466.210 ;
        RECT 351.630 465.520 354.010 466.210 ;
        RECT 354.850 465.520 360.450 466.210 ;
        RECT 361.290 465.520 363.670 466.210 ;
        RECT 364.510 465.520 366.890 466.210 ;
        RECT 367.730 465.520 373.330 466.210 ;
        RECT 374.170 465.520 376.550 466.210 ;
        RECT 377.390 465.520 379.770 466.210 ;
        RECT 380.610 465.520 386.210 466.210 ;
        RECT 387.050 465.520 389.430 466.210 ;
        RECT 390.270 465.520 395.870 466.210 ;
        RECT 396.710 465.520 399.090 466.210 ;
        RECT 399.930 465.520 402.310 466.210 ;
        RECT 403.150 465.520 408.750 466.210 ;
        RECT 409.590 465.520 411.970 466.210 ;
        RECT 412.810 465.520 415.190 466.210 ;
        RECT 416.030 465.520 421.630 466.210 ;
        RECT 422.470 465.520 424.850 466.210 ;
        RECT 425.690 465.520 431.290 466.210 ;
        RECT 432.130 465.520 434.510 466.210 ;
        RECT 435.350 465.520 437.730 466.210 ;
        RECT 438.570 465.520 444.170 466.210 ;
        RECT 445.010 465.520 447.390 466.210 ;
        RECT 448.230 465.520 450.610 466.210 ;
        RECT 451.450 465.520 457.050 466.210 ;
        RECT 457.890 465.520 458.980 466.210 ;
        RECT 0.100 4.280 458.980 465.520 ;
        RECT 0.650 3.555 3.030 4.280 ;
        RECT 3.870 3.555 6.250 4.280 ;
        RECT 7.090 3.555 12.690 4.280 ;
        RECT 13.530 3.555 15.910 4.280 ;
        RECT 16.750 3.555 19.130 4.280 ;
        RECT 19.970 3.555 25.570 4.280 ;
        RECT 26.410 3.555 28.790 4.280 ;
        RECT 29.630 3.555 32.010 4.280 ;
        RECT 32.850 3.555 38.450 4.280 ;
        RECT 39.290 3.555 41.670 4.280 ;
        RECT 42.510 3.555 48.110 4.280 ;
        RECT 48.950 3.555 51.330 4.280 ;
        RECT 52.170 3.555 54.550 4.280 ;
        RECT 55.390 3.555 60.990 4.280 ;
        RECT 61.830 3.555 64.210 4.280 ;
        RECT 65.050 3.555 67.430 4.280 ;
        RECT 68.270 3.555 73.870 4.280 ;
        RECT 74.710 3.555 77.090 4.280 ;
        RECT 77.930 3.555 83.530 4.280 ;
        RECT 84.370 3.555 86.750 4.280 ;
        RECT 87.590 3.555 89.970 4.280 ;
        RECT 90.810 3.555 96.410 4.280 ;
        RECT 97.250 3.555 99.630 4.280 ;
        RECT 100.470 3.555 102.850 4.280 ;
        RECT 103.690 3.555 109.290 4.280 ;
        RECT 110.130 3.555 112.510 4.280 ;
        RECT 113.350 3.555 118.950 4.280 ;
        RECT 119.790 3.555 122.170 4.280 ;
        RECT 123.010 3.555 125.390 4.280 ;
        RECT 126.230 3.555 131.830 4.280 ;
        RECT 132.670 3.555 135.050 4.280 ;
        RECT 135.890 3.555 138.270 4.280 ;
        RECT 139.110 3.555 144.710 4.280 ;
        RECT 145.550 3.555 147.930 4.280 ;
        RECT 148.770 3.555 154.370 4.280 ;
        RECT 155.210 3.555 157.590 4.280 ;
        RECT 158.430 3.555 160.810 4.280 ;
        RECT 161.650 3.555 167.250 4.280 ;
        RECT 168.090 3.555 170.470 4.280 ;
        RECT 171.310 3.555 173.690 4.280 ;
        RECT 174.530 3.555 180.130 4.280 ;
        RECT 180.970 3.555 183.350 4.280 ;
        RECT 184.190 3.555 189.790 4.280 ;
        RECT 190.630 3.555 193.010 4.280 ;
        RECT 193.850 3.555 196.230 4.280 ;
        RECT 197.070 3.555 202.670 4.280 ;
        RECT 203.510 3.555 205.890 4.280 ;
        RECT 206.730 3.555 209.110 4.280 ;
        RECT 209.950 3.555 215.550 4.280 ;
        RECT 216.390 3.555 218.770 4.280 ;
        RECT 219.610 3.555 225.210 4.280 ;
        RECT 226.050 3.555 228.430 4.280 ;
        RECT 229.270 3.555 231.650 4.280 ;
        RECT 232.490 3.555 238.090 4.280 ;
        RECT 238.930 3.555 241.310 4.280 ;
        RECT 242.150 3.555 244.530 4.280 ;
        RECT 245.370 3.555 250.970 4.280 ;
        RECT 251.810 3.555 254.190 4.280 ;
        RECT 255.030 3.555 260.630 4.280 ;
        RECT 261.470 3.555 263.850 4.280 ;
        RECT 264.690 3.555 267.070 4.280 ;
        RECT 267.910 3.555 273.510 4.280 ;
        RECT 274.350 3.555 276.730 4.280 ;
        RECT 277.570 3.555 279.950 4.280 ;
        RECT 280.790 3.555 286.390 4.280 ;
        RECT 287.230 3.555 289.610 4.280 ;
        RECT 290.450 3.555 296.050 4.280 ;
        RECT 296.890 3.555 299.270 4.280 ;
        RECT 300.110 3.555 302.490 4.280 ;
        RECT 303.330 3.555 308.930 4.280 ;
        RECT 309.770 3.555 312.150 4.280 ;
        RECT 312.990 3.555 315.370 4.280 ;
        RECT 316.210 3.555 321.810 4.280 ;
        RECT 322.650 3.555 325.030 4.280 ;
        RECT 325.870 3.555 331.470 4.280 ;
        RECT 332.310 3.555 334.690 4.280 ;
        RECT 335.530 3.555 337.910 4.280 ;
        RECT 338.750 3.555 344.350 4.280 ;
        RECT 345.190 3.555 347.570 4.280 ;
        RECT 348.410 3.555 350.790 4.280 ;
        RECT 351.630 3.555 357.230 4.280 ;
        RECT 358.070 3.555 360.450 4.280 ;
        RECT 361.290 3.555 366.890 4.280 ;
        RECT 367.730 3.555 370.110 4.280 ;
        RECT 370.950 3.555 373.330 4.280 ;
        RECT 374.170 3.555 379.770 4.280 ;
        RECT 380.610 3.555 382.990 4.280 ;
        RECT 383.830 3.555 386.210 4.280 ;
        RECT 387.050 3.555 392.650 4.280 ;
        RECT 393.490 3.555 395.870 4.280 ;
        RECT 396.710 3.555 402.310 4.280 ;
        RECT 403.150 3.555 405.530 4.280 ;
        RECT 406.370 3.555 408.750 4.280 ;
        RECT 409.590 3.555 415.190 4.280 ;
        RECT 416.030 3.555 418.410 4.280 ;
        RECT 419.250 3.555 421.630 4.280 ;
        RECT 422.470 3.555 428.070 4.280 ;
        RECT 428.910 3.555 431.290 4.280 ;
        RECT 432.130 3.555 437.730 4.280 ;
        RECT 438.570 3.555 440.950 4.280 ;
        RECT 441.790 3.555 444.170 4.280 ;
        RECT 445.010 3.555 450.610 4.280 ;
        RECT 451.450 3.555 453.830 4.280 ;
        RECT 454.670 3.555 457.050 4.280 ;
        RECT 457.890 3.555 458.980 4.280 ;
      LAYER met3 ;
        RECT 1.905 460.040 458.095 460.185 ;
        RECT 1.905 458.640 454.680 460.040 ;
        RECT 1.905 456.640 458.095 458.640 ;
        RECT 4.400 455.240 454.680 456.640 ;
        RECT 1.905 453.240 458.095 455.240 ;
        RECT 4.400 451.840 454.680 453.240 ;
        RECT 1.905 446.440 458.095 451.840 ;
        RECT 4.400 445.040 454.680 446.440 ;
        RECT 1.905 443.040 458.095 445.040 ;
        RECT 4.400 441.640 454.680 443.040 ;
        RECT 1.905 439.640 458.095 441.640 ;
        RECT 4.400 438.240 454.680 439.640 ;
        RECT 1.905 432.840 458.095 438.240 ;
        RECT 4.400 431.440 454.680 432.840 ;
        RECT 1.905 429.440 458.095 431.440 ;
        RECT 4.400 428.040 454.680 429.440 ;
        RECT 1.905 426.040 458.095 428.040 ;
        RECT 4.400 424.640 458.095 426.040 ;
        RECT 1.905 422.640 458.095 424.640 ;
        RECT 1.905 421.240 454.680 422.640 ;
        RECT 1.905 419.240 458.095 421.240 ;
        RECT 4.400 417.840 454.680 419.240 ;
        RECT 1.905 415.840 458.095 417.840 ;
        RECT 4.400 414.440 454.680 415.840 ;
        RECT 1.905 409.040 458.095 414.440 ;
        RECT 4.400 407.640 454.680 409.040 ;
        RECT 1.905 405.640 458.095 407.640 ;
        RECT 4.400 404.240 454.680 405.640 ;
        RECT 1.905 402.240 458.095 404.240 ;
        RECT 4.400 400.840 454.680 402.240 ;
        RECT 1.905 395.440 458.095 400.840 ;
        RECT 4.400 394.040 454.680 395.440 ;
        RECT 1.905 392.040 458.095 394.040 ;
        RECT 4.400 390.640 454.680 392.040 ;
        RECT 1.905 388.640 458.095 390.640 ;
        RECT 4.400 387.240 458.095 388.640 ;
        RECT 1.905 385.240 458.095 387.240 ;
        RECT 1.905 383.840 454.680 385.240 ;
        RECT 1.905 381.840 458.095 383.840 ;
        RECT 4.400 380.440 454.680 381.840 ;
        RECT 1.905 378.440 458.095 380.440 ;
        RECT 4.400 377.040 454.680 378.440 ;
        RECT 1.905 371.640 458.095 377.040 ;
        RECT 4.400 370.240 454.680 371.640 ;
        RECT 1.905 368.240 458.095 370.240 ;
        RECT 4.400 366.840 454.680 368.240 ;
        RECT 1.905 364.840 458.095 366.840 ;
        RECT 4.400 363.440 454.680 364.840 ;
        RECT 1.905 358.040 458.095 363.440 ;
        RECT 4.400 356.640 454.680 358.040 ;
        RECT 1.905 354.640 458.095 356.640 ;
        RECT 4.400 353.240 454.680 354.640 ;
        RECT 1.905 351.240 458.095 353.240 ;
        RECT 4.400 349.840 458.095 351.240 ;
        RECT 1.905 347.840 458.095 349.840 ;
        RECT 1.905 346.440 454.680 347.840 ;
        RECT 1.905 344.440 458.095 346.440 ;
        RECT 4.400 343.040 454.680 344.440 ;
        RECT 1.905 341.040 458.095 343.040 ;
        RECT 4.400 339.640 454.680 341.040 ;
        RECT 1.905 334.240 458.095 339.640 ;
        RECT 4.400 332.840 454.680 334.240 ;
        RECT 1.905 330.840 458.095 332.840 ;
        RECT 4.400 329.440 454.680 330.840 ;
        RECT 1.905 327.440 458.095 329.440 ;
        RECT 4.400 326.040 454.680 327.440 ;
        RECT 1.905 320.640 458.095 326.040 ;
        RECT 4.400 319.240 454.680 320.640 ;
        RECT 1.905 317.240 458.095 319.240 ;
        RECT 4.400 315.840 454.680 317.240 ;
        RECT 1.905 313.840 458.095 315.840 ;
        RECT 4.400 312.440 458.095 313.840 ;
        RECT 1.905 310.440 458.095 312.440 ;
        RECT 1.905 309.040 454.680 310.440 ;
        RECT 1.905 307.040 458.095 309.040 ;
        RECT 4.400 305.640 454.680 307.040 ;
        RECT 1.905 303.640 458.095 305.640 ;
        RECT 4.400 302.240 454.680 303.640 ;
        RECT 1.905 296.840 458.095 302.240 ;
        RECT 4.400 295.440 454.680 296.840 ;
        RECT 1.905 293.440 458.095 295.440 ;
        RECT 4.400 292.040 454.680 293.440 ;
        RECT 1.905 290.040 458.095 292.040 ;
        RECT 4.400 288.640 454.680 290.040 ;
        RECT 1.905 283.240 458.095 288.640 ;
        RECT 4.400 281.840 454.680 283.240 ;
        RECT 1.905 279.840 458.095 281.840 ;
        RECT 4.400 278.440 454.680 279.840 ;
        RECT 1.905 276.440 458.095 278.440 ;
        RECT 4.400 275.040 458.095 276.440 ;
        RECT 1.905 273.040 458.095 275.040 ;
        RECT 1.905 271.640 454.680 273.040 ;
        RECT 1.905 269.640 458.095 271.640 ;
        RECT 4.400 268.240 454.680 269.640 ;
        RECT 1.905 266.240 458.095 268.240 ;
        RECT 4.400 264.840 454.680 266.240 ;
        RECT 1.905 259.440 458.095 264.840 ;
        RECT 4.400 258.040 454.680 259.440 ;
        RECT 1.905 256.040 458.095 258.040 ;
        RECT 4.400 254.640 454.680 256.040 ;
        RECT 1.905 252.640 458.095 254.640 ;
        RECT 4.400 251.240 454.680 252.640 ;
        RECT 1.905 245.840 458.095 251.240 ;
        RECT 4.400 244.440 454.680 245.840 ;
        RECT 1.905 242.440 458.095 244.440 ;
        RECT 4.400 241.040 454.680 242.440 ;
        RECT 1.905 239.040 458.095 241.040 ;
        RECT 4.400 237.640 458.095 239.040 ;
        RECT 1.905 235.640 458.095 237.640 ;
        RECT 1.905 234.240 454.680 235.640 ;
        RECT 1.905 232.240 458.095 234.240 ;
        RECT 4.400 230.840 454.680 232.240 ;
        RECT 1.905 228.840 458.095 230.840 ;
        RECT 4.400 227.440 454.680 228.840 ;
        RECT 1.905 222.040 458.095 227.440 ;
        RECT 4.400 220.640 454.680 222.040 ;
        RECT 1.905 218.640 458.095 220.640 ;
        RECT 4.400 217.240 454.680 218.640 ;
        RECT 1.905 215.240 458.095 217.240 ;
        RECT 4.400 213.840 454.680 215.240 ;
        RECT 1.905 208.440 458.095 213.840 ;
        RECT 4.400 207.040 454.680 208.440 ;
        RECT 1.905 205.040 458.095 207.040 ;
        RECT 4.400 203.640 454.680 205.040 ;
        RECT 1.905 201.640 458.095 203.640 ;
        RECT 4.400 200.240 458.095 201.640 ;
        RECT 1.905 198.240 458.095 200.240 ;
        RECT 1.905 196.840 454.680 198.240 ;
        RECT 1.905 194.840 458.095 196.840 ;
        RECT 4.400 193.440 454.680 194.840 ;
        RECT 1.905 191.440 458.095 193.440 ;
        RECT 4.400 190.040 454.680 191.440 ;
        RECT 1.905 184.640 458.095 190.040 ;
        RECT 4.400 183.240 454.680 184.640 ;
        RECT 1.905 181.240 458.095 183.240 ;
        RECT 4.400 179.840 454.680 181.240 ;
        RECT 1.905 177.840 458.095 179.840 ;
        RECT 4.400 176.440 454.680 177.840 ;
        RECT 1.905 171.040 458.095 176.440 ;
        RECT 4.400 169.640 454.680 171.040 ;
        RECT 1.905 167.640 458.095 169.640 ;
        RECT 4.400 166.240 454.680 167.640 ;
        RECT 1.905 164.240 458.095 166.240 ;
        RECT 4.400 162.840 458.095 164.240 ;
        RECT 1.905 160.840 458.095 162.840 ;
        RECT 1.905 159.440 454.680 160.840 ;
        RECT 1.905 157.440 458.095 159.440 ;
        RECT 4.400 156.040 454.680 157.440 ;
        RECT 1.905 154.040 458.095 156.040 ;
        RECT 4.400 152.640 454.680 154.040 ;
        RECT 1.905 147.240 458.095 152.640 ;
        RECT 4.400 145.840 454.680 147.240 ;
        RECT 1.905 143.840 458.095 145.840 ;
        RECT 4.400 142.440 454.680 143.840 ;
        RECT 1.905 140.440 458.095 142.440 ;
        RECT 4.400 139.040 454.680 140.440 ;
        RECT 1.905 133.640 458.095 139.040 ;
        RECT 4.400 132.240 454.680 133.640 ;
        RECT 1.905 130.240 458.095 132.240 ;
        RECT 4.400 128.840 454.680 130.240 ;
        RECT 1.905 126.840 458.095 128.840 ;
        RECT 4.400 125.440 454.680 126.840 ;
        RECT 1.905 120.040 458.095 125.440 ;
        RECT 4.400 118.640 454.680 120.040 ;
        RECT 1.905 116.640 458.095 118.640 ;
        RECT 4.400 115.240 454.680 116.640 ;
        RECT 1.905 109.840 458.095 115.240 ;
        RECT 4.400 108.440 454.680 109.840 ;
        RECT 1.905 106.440 458.095 108.440 ;
        RECT 4.400 105.040 454.680 106.440 ;
        RECT 1.905 103.040 458.095 105.040 ;
        RECT 4.400 101.640 454.680 103.040 ;
        RECT 1.905 96.240 458.095 101.640 ;
        RECT 4.400 94.840 454.680 96.240 ;
        RECT 1.905 92.840 458.095 94.840 ;
        RECT 4.400 91.440 454.680 92.840 ;
        RECT 1.905 89.440 458.095 91.440 ;
        RECT 4.400 88.040 454.680 89.440 ;
        RECT 1.905 82.640 458.095 88.040 ;
        RECT 4.400 81.240 454.680 82.640 ;
        RECT 1.905 79.240 458.095 81.240 ;
        RECT 4.400 77.840 454.680 79.240 ;
        RECT 1.905 72.440 458.095 77.840 ;
        RECT 4.400 71.040 454.680 72.440 ;
        RECT 1.905 69.040 458.095 71.040 ;
        RECT 4.400 67.640 454.680 69.040 ;
        RECT 1.905 65.640 458.095 67.640 ;
        RECT 4.400 64.240 454.680 65.640 ;
        RECT 1.905 58.840 458.095 64.240 ;
        RECT 4.400 57.440 454.680 58.840 ;
        RECT 1.905 55.440 458.095 57.440 ;
        RECT 4.400 54.040 454.680 55.440 ;
        RECT 1.905 52.040 458.095 54.040 ;
        RECT 4.400 50.640 454.680 52.040 ;
        RECT 1.905 45.240 458.095 50.640 ;
        RECT 4.400 43.840 454.680 45.240 ;
        RECT 1.905 41.840 458.095 43.840 ;
        RECT 4.400 40.440 454.680 41.840 ;
        RECT 1.905 35.040 458.095 40.440 ;
        RECT 4.400 33.640 454.680 35.040 ;
        RECT 1.905 31.640 458.095 33.640 ;
        RECT 4.400 30.240 454.680 31.640 ;
        RECT 1.905 28.240 458.095 30.240 ;
        RECT 4.400 26.840 454.680 28.240 ;
        RECT 1.905 21.440 458.095 26.840 ;
        RECT 4.400 20.040 454.680 21.440 ;
        RECT 1.905 18.040 458.095 20.040 ;
        RECT 4.400 16.640 454.680 18.040 ;
        RECT 1.905 14.640 458.095 16.640 ;
        RECT 4.400 13.240 454.680 14.640 ;
        RECT 1.905 7.840 458.095 13.240 ;
        RECT 4.400 6.440 454.680 7.840 ;
        RECT 1.905 4.440 458.095 6.440 ;
        RECT 4.400 3.575 454.680 4.440 ;
      LAYER met4 ;
        RECT 4.895 457.600 456.450 460.185 ;
        RECT 4.895 11.055 20.640 457.600 ;
        RECT 23.040 11.055 23.940 457.600 ;
        RECT 26.340 11.055 174.240 457.600 ;
        RECT 176.640 11.055 177.540 457.600 ;
        RECT 179.940 11.055 327.840 457.600 ;
        RECT 330.240 11.055 331.140 457.600 ;
        RECT 333.540 11.055 456.450 457.600 ;
      LAYER met5 ;
        RECT 29.100 339.590 456.660 393.500 ;
        RECT 455.400 331.490 456.660 339.590 ;
        RECT 29.100 186.410 456.660 331.490 ;
        RECT 455.400 178.310 456.660 186.410 ;
        RECT 29.100 65.500 456.660 178.310 ;
  END
END picorv32
END LIBRARY

